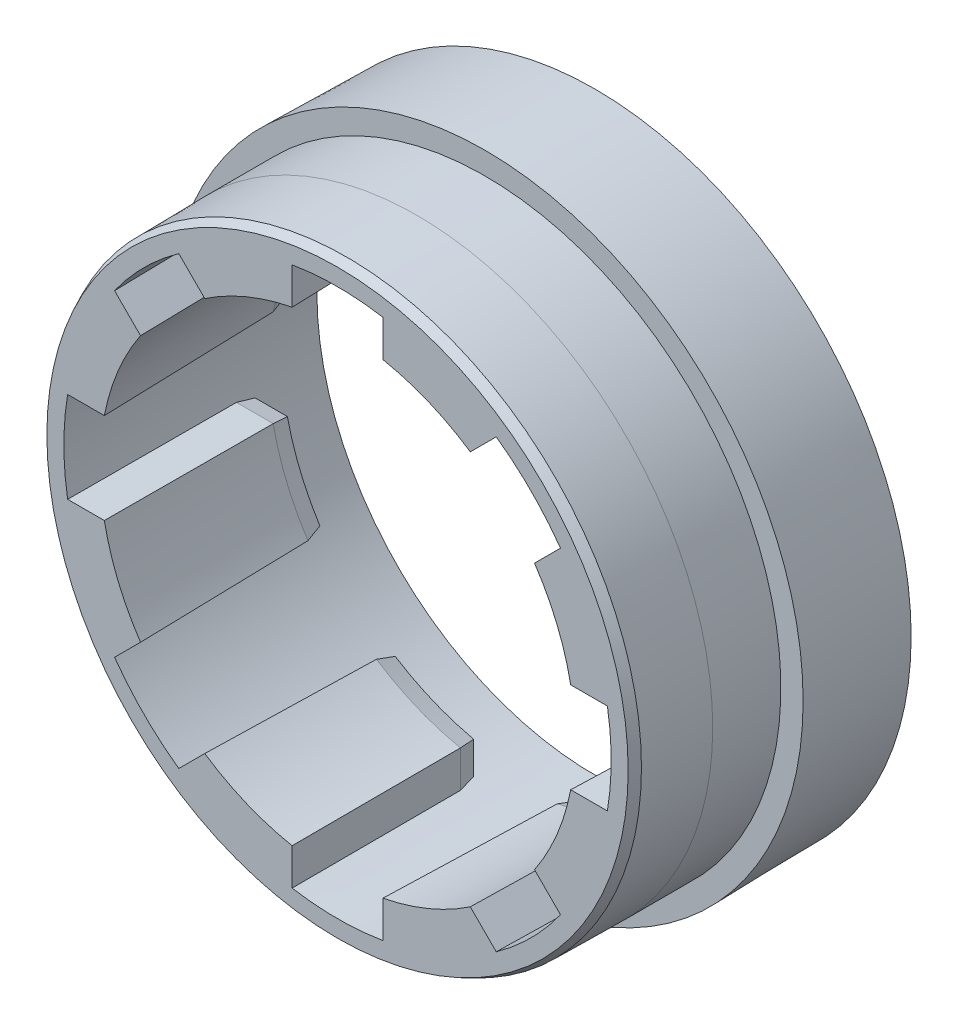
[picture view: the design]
ISO-10303-21;
HEADER;
FILE_DESCRIPTION(('STEP AP214'),'2;1');
FILE_NAME('part.step','',(''),(''),'','','');
FILE_SCHEMA(('AUTOMOTIVE_DESIGN { 1 0 10303 214 1 1 1 1 }'));
ENDSEC;
DATA;
#1=APPLICATION_CONTEXT('core data for automotive mechanical design processes');
#2=APPLICATION_PROTOCOL_DEFINITION('international standard','automotive_design',2000,#1);
#3=PRODUCT_CONTEXT('',#1,'mechanical');
#4=PRODUCT('Part','Part','',(#3));
#5=PRODUCT_RELATED_PRODUCT_CATEGORY('part','',(#4));
#6=PRODUCT_DEFINITION_FORMATION('','',#4);
#7=PRODUCT_DEFINITION_CONTEXT('part definition',#1,'design');
#8=PRODUCT_DEFINITION('design','',#6,#7);
#9=PRODUCT_DEFINITION_SHAPE('','',#8);
#10=(LENGTH_UNIT() NAMED_UNIT(*) SI_UNIT(.MILLI.,.METRE.));
#11=(NAMED_UNIT(*) PLANE_ANGLE_UNIT() SI_UNIT($,.RADIAN.));
#12=(NAMED_UNIT(*) SI_UNIT($,.STERADIAN.) SOLID_ANGLE_UNIT());
#13=UNCERTAINTY_MEASURE_WITH_UNIT(LENGTH_MEASURE(1.E-05),#10,'distance_accuracy_value','');
#14=(GEOMETRIC_REPRESENTATION_CONTEXT(3) GLOBAL_UNCERTAINTY_ASSIGNED_CONTEXT((#13)) GLOBAL_UNIT_ASSIGNED_CONTEXT((#10,
#11,#12)) REPRESENTATION_CONTEXT('',''));
#15=CARTESIAN_POINT('',(0.,0.,0.));
#16=DIRECTION('',(0.,0.,1.));
#17=DIRECTION('',(1.,0.,0.));
#18=AXIS2_PLACEMENT_3D('',#15,#16,#17);
#19=CARTESIAN_POINT('',(0.,0.,3.25));
#20=DIRECTION('',(0.,0.,-1.));
#21=DIRECTION('',(-1.,0.,0.));
#22=AXIS2_PLACEMENT_3D('',#19,#20,#21);
#23=CONICAL_SURFACE('',#22,5.23,0.0174532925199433);
#24=CARTESIAN_POINT('',(4.46424185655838,2.91006326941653,-2.42));
#25=CARTESIAN_POINT('',(4.44311687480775,2.91226582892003,-1.47499849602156));
#26=CARTESIAN_POINT('',(4.42195462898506,2.91443110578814,-0.529997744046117));
#27=CARTESIAN_POINT('',(4.37955560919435,2.91868709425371,1.36000225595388));
#28=CARTESIAN_POINT('',(4.35831883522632,2.92077780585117,2.30500150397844));
#29=CARTESIAN_POINT('',(4.33704479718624,2.92283123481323,3.25));
#30=B_SPLINE_CURVE_WITH_KNOTS('',3,(#24,#25,#26,#27,#28,#29),.UNSPECIFIED.,.F.,.F.,(4,2,4),(0.,
2.83572046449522,5.67144092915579),.UNSPECIFIED.);
#31=CARTESIAN_POINT('',(4.42173560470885,2.91443940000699,-0.520789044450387));
#32=VERTEX_POINT('',#31);
#33=CARTESIAN_POINT('',(4.33704479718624,2.92283123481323,3.25));
#34=VERTEX_POINT('',#33);
#35=EDGE_CURVE('E353',#32,#34,#30,.T.);
#36=ORIENTED_EDGE('',*,*,#35,.F.);
#37=CARTESIAN_POINT('',(0.,0.,-0.520789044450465));
#38=DIRECTION('',(0.,0.,1.));
#39=DIRECTION('',(1.,0.,0.));
#40=AXIS2_PLACEMENT_3D('',#37,#38,#39);
#41=CIRCLE('',#40,5.2958193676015);
#42=CARTESIAN_POINT('',(5.1874590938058,1.06581936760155,-0.52078904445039));
#43=VERTEX_POINT('',#42);
#44=EDGE_CURVE('E441',#32,#43,#41,.F.);
#45=ORIENTED_EDGE('',*,*,#44,.T.);
#46=CARTESIAN_POINT('',(5.13350757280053,1.00000000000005,3.25));
#47=CARTESIAN_POINT('',(5.15814058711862,1.0299003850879,1.53700808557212));
#48=CARTESIAN_POINT('',(5.18260361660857,1.05980081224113,-0.175986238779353));
#49=CARTESIAN_POINT('',(5.23118970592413,1.11960175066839,-3.60197970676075));
#50=CARTESIAN_POINT('',(5.25531276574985,1.14950226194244,-5.31497885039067));
#51=CARTESIAN_POINT('',(5.27926584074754,1.17940281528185,-7.02798040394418));
#52=B_SPLINE_CURVE_WITH_KNOTS('',3,(#46,#47,#48,#49,#50,#51),.UNSPECIFIED.,.F.,.F.,(4,2,4),(0.,
5.14028970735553,10.2805794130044),.UNSPECIFIED.);
#53=CARTESIAN_POINT('',(5.13350757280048,1.00000000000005,3.25));
#54=VERTEX_POINT('',#53);
#55=EDGE_CURVE('E767',#54,#43,#52,.T.);
#56=ORIENTED_EDGE('',*,*,#55,.F.);
#57=CARTESIAN_POINT('',(0.,0.,3.25));
#58=DIRECTION('',(0.,0.,-1.));
#59=DIRECTION('',(-1.,0.,0.));
#60=AXIS2_PLACEMENT_3D('',#57,#58,#59);
#61=CIRCLE('',#60,5.23);
#62=EDGE_CURVE('E428',#34,#54,#61,.T.);
#63=ORIENTED_EDGE('',*,*,#62,.F.);
#64=EDGE_LOOP('',(#36,#45,#56,#63));
#65=FACE_BOUND('',#64,.T.);
#66=ADVANCED_FACE('F17',(#65),#23,.F.);
#67=CARTESIAN_POINT('',(0.,0.,3.25));
#68=DIRECTION('',(0.,0.,-1.));
#69=DIRECTION('',(-1.,0.,0.));
#70=AXIS2_PLACEMENT_3D('',#67,#68,#69);
#71=CONICAL_SURFACE('',#70,5.23,0.0174532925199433);
#72=CARTESIAN_POINT('',(5.21442116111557,-1.09897021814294,-2.42));
#73=CARTESIAN_POINT('',(5.20104098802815,-1.08247515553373,-1.47499849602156));
#74=CARTESIAN_POINT('',(5.18760810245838,-1.06598010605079,-0.529997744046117));
#75=CARTESIAN_POINT('',(5.16063690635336,-1.03299003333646,1.36000225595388));
#76=CARTESIAN_POINT('',(5.14709859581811,-1.01649501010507,2.30500150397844));
#77=CARTESIAN_POINT('',(5.1335075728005,-0.999999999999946,3.25));
#78=B_SPLINE_CURVE_WITH_KNOTS('',3,(#72,#73,#74,#75,#76,#77),.UNSPECIFIED.,.F.,.F.,(4,2,4),(0.,
2.83572046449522,5.67144092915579),.UNSPECIFIED.);
#79=CARTESIAN_POINT('',(5.18745909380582,-1.06581936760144,-0.520789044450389));
#80=VERTEX_POINT('',#79);
#81=CARTESIAN_POINT('',(5.1335075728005,-0.999999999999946,3.25));
#82=VERTEX_POINT('',#81);
#83=EDGE_CURVE('E364',#80,#82,#78,.T.);
#84=ORIENTED_EDGE('',*,*,#83,.F.);
#85=CARTESIAN_POINT('',(0.,0.,-0.520789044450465));
#86=DIRECTION('',(0.,0.,1.));
#87=DIRECTION('',(1.,0.,0.));
#88=AXIS2_PLACEMENT_3D('',#85,#86,#87);
#89=CIRCLE('',#88,5.2958193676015);
#90=CARTESIAN_POINT('',(4.42173560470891,-2.9144394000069,-0.520789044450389));
#91=VERTEX_POINT('',#90);
#92=EDGE_CURVE('E1719',#80,#91,#89,.F.);
#93=ORIENTED_EDGE('',*,*,#92,.T.);
#94=CARTESIAN_POINT('',(4.33704479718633,-2.92283123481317,3.25));
#95=CARTESIAN_POINT('',(4.37560573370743,-2.91910664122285,1.53700808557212));
#96=CARTESIAN_POINT('',(4.41404650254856,-2.91526182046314,-0.175986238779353));
#97=CARTESIAN_POINT('',(4.49068770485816,-2.90733172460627,-3.60197970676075));
#98=CARTESIAN_POINT('',(4.52888813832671,-2.90324644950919,-5.31497885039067));
#99=CARTESIAN_POINT('',(4.56696840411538,-2.89904094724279,-7.02798040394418));
#100=B_SPLINE_CURVE_WITH_KNOTS('',3,(#94,#95,#96,#97,#98,#99),.UNSPECIFIED.,.F.,.F.,(4,2,4),(0.,
5.14028970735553,10.2805794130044),.UNSPECIFIED.);
#101=CARTESIAN_POINT('',(4.3370447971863,-2.92283123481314,3.25));
#102=VERTEX_POINT('',#101);
#103=EDGE_CURVE('E808',#102,#91,#100,.T.);
#104=ORIENTED_EDGE('',*,*,#103,.F.);
#105=EDGE_CURVE('E1029',#82,#102,#61,.T.);
#106=ORIENTED_EDGE('',*,*,#105,.F.);
#107=EDGE_LOOP('',(#84,#93,#104,#106));
#108=FACE_BOUND('',#107,.T.);
#109=ADVANCED_FACE('F741',(#108),#71,.F.);
#110=CARTESIAN_POINT('',(0.,0.,3.25));
#111=DIRECTION('',(0.,0.,-1.));
#112=DIRECTION('',(-1.,0.,0.));
#113=AXIS2_PLACEMENT_3D('',#110,#111,#112);
#114=CONICAL_SURFACE('',#113,5.23,0.0174532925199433);
#115=CARTESIAN_POINT('',(2.91006326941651,-4.46424185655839,-2.42));
#116=CARTESIAN_POINT('',(2.91226582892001,-4.44311687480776,-1.47499849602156));
#117=CARTESIAN_POINT('',(2.91443110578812,-4.42195462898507,-0.529997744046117));
#118=CARTESIAN_POINT('',(2.91868709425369,-4.37955560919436,1.36000225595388));
#119=CARTESIAN_POINT('',(2.92077780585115,-4.35831883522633,2.30500150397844));
#120=CARTESIAN_POINT('',(2.92283123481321,-4.33704479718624,3.25));
#121=B_SPLINE_CURVE_WITH_KNOTS('',3,(#115,#116,#117,#118,#119,#120),.UNSPECIFIED.,.F.,.F.,(4,2,
4),(0.,2.83572046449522,5.67144092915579),.UNSPECIFIED.);
#122=CARTESIAN_POINT('',(2.91443940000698,-4.42173560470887,-0.520789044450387));
#123=VERTEX_POINT('',#122);
#124=CARTESIAN_POINT('',(2.92283123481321,-4.33704479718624,3.25));
#125=VERTEX_POINT('',#124);
#126=EDGE_CURVE('E375',#123,#125,#121,.T.);
#127=ORIENTED_EDGE('',*,*,#126,.F.);
#128=CARTESIAN_POINT('',(0.,0.,-0.520789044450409));
#129=DIRECTION('',(0.,0.,1.));
#130=DIRECTION('',(1.,0.,0.));
#131=AXIS2_PLACEMENT_3D('',#128,#129,#130);
#132=CIRCLE('',#131,5.29581936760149);
#133=CARTESIAN_POINT('',(1.06581936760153,-5.18745909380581,-0.52078904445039));
#134=VERTEX_POINT('',#133);
#135=EDGE_CURVE('E1057',#123,#134,#132,.F.);
#136=ORIENTED_EDGE('',*,*,#135,.T.);
#137=CARTESIAN_POINT('',(1.00000000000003,-5.13350757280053,3.25));
#138=CARTESIAN_POINT('',(1.02990038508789,-5.15814058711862,1.53700808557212));
#139=CARTESIAN_POINT('',(1.05980081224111,-5.18260361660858,-0.175986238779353));
#140=CARTESIAN_POINT('',(1.11960175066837,-5.23118970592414,-3.60197970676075));
#141=CARTESIAN_POINT('',(1.14950226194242,-5.25531276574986,-5.31497885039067));
#142=CARTESIAN_POINT('',(1.17940281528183,-5.27926584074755,-7.02798040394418));
#143=B_SPLINE_CURVE_WITH_KNOTS('',3,(#137,#138,#139,#140,#141,#142),.UNSPECIFIED.,.F.,.F.,(4,2,
4),(0.,5.14028970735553,10.2805794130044),.UNSPECIFIED.);
#144=CARTESIAN_POINT('',(1.00000000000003,-5.13350757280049,3.25));
#145=VERTEX_POINT('',#144);
#146=EDGE_CURVE('E453',#145,#134,#143,.T.);
#147=ORIENTED_EDGE('',*,*,#146,.F.);
#148=EDGE_CURVE('E1030',#125,#145,#61,.T.);
#149=ORIENTED_EDGE('',*,*,#148,.F.);
#150=EDGE_LOOP('',(#127,#136,#147,#149));
#151=FACE_BOUND('',#150,.T.);
#152=ADVANCED_FACE('F748',(#151),#114,.F.);
#153=CARTESIAN_POINT('',(0.,0.,3.25));
#154=DIRECTION('',(0.,0.,-1.));
#155=DIRECTION('',(-1.,0.,0.));
#156=AXIS2_PLACEMENT_3D('',#153,#154,#155);
#157=CONICAL_SURFACE('',#156,5.23,0.0174532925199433);
#158=CARTESIAN_POINT('',(-1.09897021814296,-5.21442116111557,-2.42));
#159=CARTESIAN_POINT('',(-1.08247515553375,-5.20104098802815,-1.47499849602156));
#160=CARTESIAN_POINT('',(-1.0659801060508,-5.18760810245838,-0.529997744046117));
#161=CARTESIAN_POINT('',(-1.03299003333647,-5.16063690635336,1.36000225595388));
#162=CARTESIAN_POINT('',(-1.01649501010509,-5.1470985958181,2.30500150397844));
#163=CARTESIAN_POINT('',(-0.999999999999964,-5.1335075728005,3.25));
#164=B_SPLINE_CURVE_WITH_KNOTS('',3,(#158,#159,#160,#161,#162,#163),.UNSPECIFIED.,.F.,.F.,(4,2,
4),(0.,2.83572046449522,5.67144092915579),.UNSPECIFIED.);
#165=CARTESIAN_POINT('',(-1.06581936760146,-5.18745909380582,-0.520789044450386));
#166=VERTEX_POINT('',#165);
#167=CARTESIAN_POINT('',(-0.999999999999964,-5.1335075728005,3.25));
#168=VERTEX_POINT('',#167);
#169=EDGE_CURVE('E386',#166,#168,#164,.T.);
#170=ORIENTED_EDGE('',*,*,#169,.F.);
#171=CARTESIAN_POINT('',(0.,0.,-0.520789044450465));
#172=DIRECTION('',(0.,0.,1.));
#173=DIRECTION('',(1.,0.,0.));
#174=AXIS2_PLACEMENT_3D('',#171,#172,#173);
#175=CIRCLE('',#174,5.2958193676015);
#176=CARTESIAN_POINT('',(-2.91443940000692,-4.4217356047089,-0.520789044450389));
#177=VERTEX_POINT('',#176);
#178=EDGE_CURVE('E1048',#166,#177,#175,.F.);
#179=ORIENTED_EDGE('',*,*,#178,.T.);
#180=CARTESIAN_POINT('',(-2.92283123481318,-4.33704479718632,3.25));
#181=CARTESIAN_POINT('',(-2.91910664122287,-4.37560573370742,1.53700808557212));
#182=CARTESIAN_POINT('',(-2.91526182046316,-4.41404650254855,-0.175986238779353));
#183=CARTESIAN_POINT('',(-2.90733172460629,-4.49068770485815,-3.60197970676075));
#184=CARTESIAN_POINT('',(-2.9032464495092,-4.5288881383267,-5.31497885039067));
#185=CARTESIAN_POINT('',(-2.89904094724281,-4.56696840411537,-7.02798040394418));
#186=B_SPLINE_CURVE_WITH_KNOTS('',3,(#180,#181,#182,#183,#184,#185),.UNSPECIFIED.,.F.,.F.,(4,2,
4),(0.,5.14028970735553,10.2805794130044),.UNSPECIFIED.);
#187=CARTESIAN_POINT('',(-2.92283123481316,-4.33704479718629,3.25));
#188=VERTEX_POINT('',#187);
#189=EDGE_CURVE('E840',#188,#177,#186,.T.);
#190=ORIENTED_EDGE('',*,*,#189,.F.);
#191=EDGE_CURVE('E982',#168,#188,#61,.T.);
#192=ORIENTED_EDGE('',*,*,#191,.F.);
#193=EDGE_LOOP('',(#170,#179,#190,#192));
#194=FACE_BOUND('',#193,.T.);
#195=ADVANCED_FACE('F831',(#194),#157,.F.);
#196=CARTESIAN_POINT('',(0.,0.,3.25));
#197=DIRECTION('',(0.,0.,-1.));
#198=DIRECTION('',(-1.,0.,0.));
#199=AXIS2_PLACEMENT_3D('',#196,#197,#198);
#200=CONICAL_SURFACE('',#199,5.23,0.0174532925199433);
#201=CARTESIAN_POINT('',(-4.4642418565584,-2.91006326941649,-2.42));
#202=CARTESIAN_POINT('',(-4.44311687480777,-2.91226582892,-1.47499849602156));
#203=CARTESIAN_POINT('',(-4.42195462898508,-2.91443110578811,-0.529997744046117));
#204=CARTESIAN_POINT('',(-4.37955560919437,-2.91868709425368,1.36000225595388));
#205=CARTESIAN_POINT('',(-4.35831883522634,-2.92077780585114,2.30500150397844));
#206=CARTESIAN_POINT('',(-4.33704479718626,-2.9228312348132,3.25));
#207=B_SPLINE_CURVE_WITH_KNOTS('',3,(#201,#202,#203,#204,#205,#206),.UNSPECIFIED.,.F.,.F.,(4,2,
4),(0.,2.83572046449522,5.67144092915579),.UNSPECIFIED.);
#208=CARTESIAN_POINT('',(-4.42173560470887,-2.91443940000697,-0.520789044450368));
#209=VERTEX_POINT('',#208);
#210=CARTESIAN_POINT('',(-4.33704479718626,-2.9228312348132,3.25));
#211=VERTEX_POINT('',#210);
#212=EDGE_CURVE('E397',#209,#211,#207,.T.);
#213=ORIENTED_EDGE('',*,*,#212,.F.);
#214=CARTESIAN_POINT('',(0.,0.,-0.520789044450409));
#215=DIRECTION('',(0.,0.,1.));
#216=DIRECTION('',(1.,0.,0.));
#217=AXIS2_PLACEMENT_3D('',#214,#215,#216);
#218=CIRCLE('',#217,5.29581936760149);
#219=CARTESIAN_POINT('',(-5.18745909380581,-1.06581936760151,-0.520789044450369));
#220=VERTEX_POINT('',#219);
#221=EDGE_CURVE('E1054',#209,#220,#218,.F.);
#222=ORIENTED_EDGE('',*,*,#221,.T.);
#223=CARTESIAN_POINT('',(-5.13350757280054,-1.00000000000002,3.25));
#224=CARTESIAN_POINT('',(-5.15814058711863,-1.02990038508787,1.53700808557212));
#225=CARTESIAN_POINT('',(-5.18260361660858,-1.05980081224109,-0.175986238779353));
#226=CARTESIAN_POINT('',(-5.23118970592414,-1.11960175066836,-3.60197970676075));
#227=CARTESIAN_POINT('',(-5.25531276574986,-1.1495022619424,-5.31497885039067));
#228=CARTESIAN_POINT('',(-5.27926584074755,-1.17940281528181,-7.02798040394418));
#229=B_SPLINE_CURVE_WITH_KNOTS('',3,(#223,#224,#225,#226,#227,#228),.UNSPECIFIED.,.F.,.F.,(4,2,
4),(0.,5.14028970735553,10.2805794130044),.UNSPECIFIED.);
#230=CARTESIAN_POINT('',(-5.13350757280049,-1.00000000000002,3.25));
#231=VERTEX_POINT('',#230);
#232=EDGE_CURVE('E878',#231,#220,#229,.T.);
#233=ORIENTED_EDGE('',*,*,#232,.F.);
#234=EDGE_CURVE('E981',#211,#231,#61,.T.);
#235=ORIENTED_EDGE('',*,*,#234,.F.);
#236=EDGE_LOOP('',(#213,#222,#233,#235));
#237=FACE_BOUND('',#236,.T.);
#238=ADVANCED_FACE('F836',(#237),#200,.F.);
#239=CARTESIAN_POINT('',(0.,0.,3.25));
#240=DIRECTION('',(0.,0.,-1.));
#241=DIRECTION('',(-1.,0.,0.));
#242=AXIS2_PLACEMENT_3D('',#239,#240,#241);
#243=CONICAL_SURFACE('',#242,5.23,0.0174532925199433);
#244=CARTESIAN_POINT('',(-5.21442116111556,1.09897021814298,-2.42));
#245=CARTESIAN_POINT('',(-5.20104098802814,1.08247515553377,-1.47499849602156));
#246=CARTESIAN_POINT('',(-5.18760810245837,1.06598010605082,-0.529997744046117));
#247=CARTESIAN_POINT('',(-5.16063690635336,1.03299003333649,1.36000225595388));
#248=CARTESIAN_POINT('',(-5.1470985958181,1.01649501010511,2.30500150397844));
#249=CARTESIAN_POINT('',(-5.1335075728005,0.999999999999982,3.25));
#250=B_SPLINE_CURVE_WITH_KNOTS('',3,(#244,#245,#246,#247,#248,#249),.UNSPECIFIED.,.F.,.F.,(4,2,
4),(0.,2.83572046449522,5.67144092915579),.UNSPECIFIED.);
#251=CARTESIAN_POINT('',(-5.18745909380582,1.06581936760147,-0.52078904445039));
#252=VERTEX_POINT('',#251);
#253=CARTESIAN_POINT('',(-5.1335075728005,0.999999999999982,3.25));
#254=VERTEX_POINT('',#253);
#255=EDGE_CURVE('E408',#252,#254,#250,.T.);
#256=ORIENTED_EDGE('',*,*,#255,.F.);
#257=CARTESIAN_POINT('',(0.,0.,-0.520789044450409));
#258=DIRECTION('',(0.,0.,1.));
#259=DIRECTION('',(1.,0.,0.));
#260=AXIS2_PLACEMENT_3D('',#257,#258,#259);
#261=CIRCLE('',#260,5.29581936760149);
#262=CARTESIAN_POINT('',(-4.42173560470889,2.91443940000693,-0.520789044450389));
#263=VERTEX_POINT('',#262);
#264=EDGE_CURVE('E1066',#252,#263,#261,.F.);
#265=ORIENTED_EDGE('',*,*,#264,.T.);
#266=CARTESIAN_POINT('',(-4.33704479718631,2.9228312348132,3.25));
#267=CARTESIAN_POINT('',(-4.37560573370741,2.91910664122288,1.53700808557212));
#268=CARTESIAN_POINT('',(-4.41404650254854,2.91526182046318,-0.175986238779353));
#269=CARTESIAN_POINT('',(-4.49068770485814,2.9073317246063,-3.60197970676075));
#270=CARTESIAN_POINT('',(-4.52888813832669,2.90324644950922,-5.31497885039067));
#271=CARTESIAN_POINT('',(-4.56696840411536,2.89904094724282,-7.02798040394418));
#272=B_SPLINE_CURVE_WITH_KNOTS('',3,(#266,#267,#268,#269,#270,#271),.UNSPECIFIED.,.F.,.F.,(4,2,
4),(0.,5.14028970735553,10.2805794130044),.UNSPECIFIED.);
#273=CARTESIAN_POINT('',(-4.33704479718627,2.92283123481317,3.25));
#274=VERTEX_POINT('',#273);
#275=EDGE_CURVE('E918',#274,#263,#272,.T.);
#276=ORIENTED_EDGE('',*,*,#275,.F.);
#277=EDGE_CURVE('E977',#254,#274,#61,.T.);
#278=ORIENTED_EDGE('',*,*,#277,.F.);
#279=EDGE_LOOP('',(#256,#265,#276,#278));
#280=FACE_BOUND('',#279,.T.);
#281=ADVANCED_FACE('F954',(#280),#243,.F.);
#282=CARTESIAN_POINT('',(0.,0.,3.25));
#283=DIRECTION('',(0.,0.,-1.));
#284=DIRECTION('',(-1.,0.,0.));
#285=AXIS2_PLACEMENT_3D('',#282,#283,#284);
#286=CONICAL_SURFACE('',#285,5.23,0.0174532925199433);
#287=CARTESIAN_POINT('',(-2.91006326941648,4.46424185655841,-2.42));
#288=CARTESIAN_POINT('',(-2.91226582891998,4.44311687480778,-1.47499849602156));
#289=CARTESIAN_POINT('',(-2.91443110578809,4.42195462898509,-0.529997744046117));
#290=CARTESIAN_POINT('',(-2.91868709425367,4.37955560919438,1.36000225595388));
#291=CARTESIAN_POINT('',(-2.92077780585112,4.35831883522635,2.30500150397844));
#292=CARTESIAN_POINT('',(-2.92283123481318,4.33704479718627,3.25));
#293=B_SPLINE_CURVE_WITH_KNOTS('',3,(#287,#288,#289,#290,#291,#292),.UNSPECIFIED.,.F.,.F.,(4,2,
4),(0.,2.83572046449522,5.67144092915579),.UNSPECIFIED.);
#294=CARTESIAN_POINT('',(-2.91443940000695,4.42173560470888,-0.520789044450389));
#295=VERTEX_POINT('',#294);
#296=CARTESIAN_POINT('',(-2.92283123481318,4.33704479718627,3.25));
#297=VERTEX_POINT('',#296);
#298=EDGE_CURVE('E419',#295,#297,#293,.T.);
#299=ORIENTED_EDGE('',*,*,#298,.F.);
#300=CARTESIAN_POINT('',(0.,0.,-0.520789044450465));
#301=DIRECTION('',(0.,0.,1.));
#302=DIRECTION('',(1.,0.,0.));
#303=AXIS2_PLACEMENT_3D('',#300,#301,#302);
#304=CIRCLE('',#303,5.2958193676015);
#305=CARTESIAN_POINT('',(-1.06581936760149,5.18745909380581,-0.52078904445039));
#306=VERTEX_POINT('',#305);
#307=EDGE_CURVE('E1071',#295,#306,#304,.F.);
#308=ORIENTED_EDGE('',*,*,#307,.T.);
#309=CARTESIAN_POINT('',(-1.,5.13350757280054,3.25));
#310=CARTESIAN_POINT('',(-1.02990038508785,5.15814058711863,1.53700808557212));
#311=CARTESIAN_POINT('',(-1.05980081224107,5.18260361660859,-0.175986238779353));
#312=CARTESIAN_POINT('',(-1.11960175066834,5.23118970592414,-3.60197970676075));
#313=CARTESIAN_POINT('',(-1.14950226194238,5.25531276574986,-5.31497885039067));
#314=CARTESIAN_POINT('',(-1.17940281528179,5.27926584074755,-7.02798040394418));
#315=B_SPLINE_CURVE_WITH_KNOTS('',3,(#309,#310,#311,#312,#313,#314),.UNSPECIFIED.,.F.,.F.,(4,2,
4),(0.,5.14028970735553,10.2805794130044),.UNSPECIFIED.);
#316=CARTESIAN_POINT('',(-1.,5.13350757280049,3.25));
#317=VERTEX_POINT('',#316);
#318=EDGE_CURVE('E945',#317,#306,#315,.T.);
#319=ORIENTED_EDGE('',*,*,#318,.F.);
#320=EDGE_CURVE('E429',#297,#317,#61,.T.);
#321=ORIENTED_EDGE('',*,*,#320,.F.);
#322=EDGE_LOOP('',(#299,#308,#319,#321));
#323=FACE_BOUND('',#322,.T.);
#324=ADVANCED_FACE('F951',(#323),#286,.F.);
#325=CARTESIAN_POINT('',(0.,0.,3.25));
#326=DIRECTION('',(0.,0.,-1.));
#327=DIRECTION('',(-1.,0.,0.));
#328=AXIS2_PLACEMENT_3D('',#325,#326,#327);
#329=CONICAL_SURFACE('',#328,5.23,0.0174532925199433);
#330=CARTESIAN_POINT('',(1.09897021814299,5.21442116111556,-2.42));
#331=CARTESIAN_POINT('',(1.08247515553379,5.20104098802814,-1.47499849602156));
#332=CARTESIAN_POINT('',(1.06598010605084,5.18760810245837,-0.529997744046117));
#333=CARTESIAN_POINT('',(1.03299003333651,5.16063690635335,1.36000225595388));
#334=CARTESIAN_POINT('',(1.01649501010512,5.1470985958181,2.30500150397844));
#335=CARTESIAN_POINT('',(1.,5.13350757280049,3.25));
#336=B_SPLINE_CURVE_WITH_KNOTS('',3,(#330,#331,#332,#333,#334,#335),.UNSPECIFIED.,.F.,.F.,(4,2,
4),(0.,2.83572046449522,5.67144092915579),.UNSPECIFIED.);
#337=CARTESIAN_POINT('',(1.06581936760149,5.18745909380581,-0.520789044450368));
#338=VERTEX_POINT('',#337);
#339=CARTESIAN_POINT('',(1.,5.13350757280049,3.25));
#340=VERTEX_POINT('',#339);
#341=EDGE_CURVE('E983',#338,#340,#336,.T.);
#342=ORIENTED_EDGE('',*,*,#341,.F.);
#343=CARTESIAN_POINT('',(0.,0.,-0.520789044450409));
#344=DIRECTION('',(0.,0.,1.));
#345=DIRECTION('',(1.,0.,0.));
#346=AXIS2_PLACEMENT_3D('',#343,#344,#345);
#347=CIRCLE('',#346,5.29581936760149);
#348=CARTESIAN_POINT('',(2.91443940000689,4.42173560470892,-0.520789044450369));
#349=VERTEX_POINT('',#348);
#350=EDGE_CURVE('E1077',#338,#349,#347,.F.);
#351=ORIENTED_EDGE('',*,*,#350,.T.);
#352=CARTESIAN_POINT('',(2.92283123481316,4.33704479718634,3.25));
#353=CARTESIAN_POINT('',(2.91910664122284,4.37560573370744,1.53700808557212));
#354=CARTESIAN_POINT('',(2.91526182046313,4.41404650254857,-0.175986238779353));
#355=CARTESIAN_POINT('',(2.90733172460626,4.49068770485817,-3.60197970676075));
#356=CARTESIAN_POINT('',(2.90324644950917,4.52888813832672,-5.31497885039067));
#357=CARTESIAN_POINT('',(2.89904094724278,4.56696840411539,-7.02798040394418));
#358=B_SPLINE_CURVE_WITH_KNOTS('',3,(#352,#353,#354,#355,#356,#357),.UNSPECIFIED.,.F.,.F.,(4,2,
4),(0.,5.14028970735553,10.2805794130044),.UNSPECIFIED.);
#359=CARTESIAN_POINT('',(2.92283123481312,4.33704479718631,3.25));
#360=VERTEX_POINT('',#359);
#361=EDGE_CURVE('E1002',#360,#349,#358,.T.);
#362=ORIENTED_EDGE('',*,*,#361,.F.);
#363=EDGE_CURVE('E344',#340,#360,#61,.T.);
#364=ORIENTED_EDGE('',*,*,#363,.F.);
#365=EDGE_LOOP('',(#342,#351,#362,#364));
#366=FACE_BOUND('',#365,.T.);
#367=ADVANCED_FACE('F754',(#366),#329,.F.);
#368=CARTESIAN_POINT('',(1.,5.,3.25));
#369=DIRECTION('',(-0.999847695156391,0.,-0.0174524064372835));
#370=DIRECTION('',(-0.0174524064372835,0.,0.999847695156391));
#371=AXIS2_PLACEMENT_3D('',#368,#369,#370);
#372=PLANE('',#371);
#373=CARTESIAN_POINT('',(1.09897021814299,6.02455605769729,-2.42));
#374=CARTESIAN_POINT('',(1.08247515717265,6.01079841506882,-1.47499858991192));
#375=CARTESIAN_POINT('',(1.06598010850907,5.99699266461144,-0.529997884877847));
#376=CARTESIAN_POINT('',(1.03299003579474,5.96928494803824,1.36000211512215));
#377=CARTESIAN_POINT('',(1.01649501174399,5.95538298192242,2.30500141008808));
#378=CARTESIAN_POINT('',(1.,5.94143290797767,3.25));
#379=B_SPLINE_CURVE_WITH_KNOTS('',3,(#373,#374,#375,#376,#377,#378),.UNSPECIFIED.,.F.,.F.,(4,2,
4),(0.,2.83573644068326,5.67147288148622),.UNSPECIFIED.);
#380=CARTESIAN_POINT('',(1.06581936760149,5.99684163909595,-0.520789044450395));
#381=VERTEX_POINT('',#380);
#382=CARTESIAN_POINT('',(1.,5.94143290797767,3.25));
#383=VERTEX_POINT('',#382);
#384=EDGE_CURVE('E991',#381,#383,#379,.T.);
#385=ORIENTED_EDGE('',*,*,#384,.F.);
#386=DIRECTION('',(0.,1.,0.));
#387=VECTOR('',#386,1.);
#388=CARTESIAN_POINT('',(1.06581936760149,5.29520923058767,-0.520789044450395));
#389=LINE('',#388,#387);
#390=EDGE_CURVE('E1159',#381,#338,#389,.F.);
#391=ORIENTED_EDGE('',*,*,#390,.T.);
#392=ORIENTED_EDGE('',*,*,#341,.T.);
#393=DIRECTION('',(0.,1.,0.));
#394=VECTOR('',#393,1.);
#395=CARTESIAN_POINT('',(1.,5.,3.25));
#396=LINE('',#395,#394);
#397=EDGE_CURVE('E422',#340,#383,#396,.T.);
#398=ORIENTED_EDGE('',*,*,#397,.T.);
#399=EDGE_LOOP('',(#385,#391,#392,#398));
#400=FACE_BOUND('',#399,.T.);
#401=ADVANCED_FACE('F1007',(#400),#372,.T.);
#402=CARTESIAN_POINT('',(-1.,5.,3.25));
#403=DIRECTION('',(0.999847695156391,0.,-0.0174524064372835));
#404=DIRECTION('',(-0.0174524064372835,0.,-0.999847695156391));
#405=AXIS2_PLACEMENT_3D('',#402,#403,#404);
#406=PLANE('',#405);
#407=ORIENTED_EDGE('',*,*,#318,.T.);
#408=DIRECTION('',(0.,-1.,0.));
#409=VECTOR('',#408,1.);
#410=CARTESIAN_POINT('',(-1.06581936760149,6.00267778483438,-0.520789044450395));
#411=LINE('',#410,#409);
#412=CARTESIAN_POINT('',(-1.06581936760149,5.99684163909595,-0.520789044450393));
#413=VERTEX_POINT('',#412);
#414=EDGE_CURVE('E1146',#306,#413,#411,.F.);
#415=ORIENTED_EDGE('',*,*,#414,.T.);
#416=CARTESIAN_POINT('',(-1.56885999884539,6.40450372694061,-29.3399675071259));
#417=CARTESIAN_POINT('',(-1.52145465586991,6.36730875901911,-26.6241172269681));
#418=CARTESIAN_POINT('',(-1.47404938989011,6.32979091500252,-23.9082713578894));
#419=CARTESIAN_POINT('',(-1.37923902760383,6.25407165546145,-18.4765893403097));
#420=CARTESIAN_POINT('',(-1.33183393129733,6.21587023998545,-15.760753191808));
#421=CARTESIAN_POINT('',(-1.23702391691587,6.13874601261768,-10.3290911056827));
#422=CARTESIAN_POINT('',(-1.18961899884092,6.09982320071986,-7.61326516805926));
#423=CARTESIAN_POINT('',(-1.09480935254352,6.02121264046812,-2.18162416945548));
#424=CARTESIAN_POINT('',(-1.04740462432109,5.98152489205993,0.534190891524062));
#425=CARTESIAN_POINT('',(-1.,5.94143290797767,3.25));
#426=B_SPLINE_CURVE_WITH_KNOTS('',3,(#416,#417,#418,#419,#420,#421,#422,#423,#424,#425),
.UNSPECIFIED.,.F.,.F.,(4,2,2,2,4),(0.,8.14955588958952,16.2991112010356,24.4486665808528,
32.5982225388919),.UNSPECIFIED.);
#427=CARTESIAN_POINT('',(-1.,5.94143290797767,3.25));
#428=VERTEX_POINT('',#427);
#429=EDGE_CURVE('E444',#413,#428,#426,.T.);
#430=ORIENTED_EDGE('',*,*,#429,.T.);
#431=DIRECTION('',(0.,-1.,0.));
#432=VECTOR('',#431,1.);
#433=CARTESIAN_POINT('',(-1.,5.,3.25));
#434=LINE('',#433,#432);
#435=EDGE_CURVE('E418',#428,#317,#434,.T.);
#436=ORIENTED_EDGE('',*,*,#435,.T.);
#437=EDGE_LOOP('',(#407,#415,#430,#436));
#438=FACE_BOUND('',#437,.T.);
#439=ADVANCED_FACE('F935',(#438),#406,.T.);
#440=CARTESIAN_POINT('',(-2.8284271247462,4.24264068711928,3.25));
#441=DIRECTION('',(-0.706999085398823,-0.706999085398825,-0.0174524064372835));
#442=DIRECTION('',(0.707106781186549,-0.707106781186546,0.));
#443=AXIS2_PLACEMENT_3D('',#440,#441,#442);
#444=PLANE('',#443);
#445=CARTESIAN_POINT('',(-3.48291514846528,5.03709373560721,-2.42));
#446=CARTESIAN_POINT('',(-3.48485079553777,5.01570184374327,-1.47499858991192));
#447=CARTESIAN_POINT('',(-3.48675241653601,4.99427594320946,-0.529997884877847));
#448=CARTESIAN_POINT('',(-3.49048760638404,4.95135612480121,1.36000211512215));
#449=CARTESIAN_POINT('',(-3.49232117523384,4.92986220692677,2.30500141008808));
#450=CARTESIAN_POINT('',(-3.49412071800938,4.90833428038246,3.25));
#451=B_SPLINE_CURVE_WITH_KNOTS('',3,(#445,#446,#447,#448,#449,#450),.UNSPECIFIED.,.F.,.F.,(4,2,
4),(0.,2.83573644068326,5.67147288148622),.UNSPECIFIED.);
#452=CARTESIAN_POINT('',(-3.48675928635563,4.99405549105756,-0.520789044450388));
#453=VERTEX_POINT('',#452);
#454=CARTESIAN_POINT('',(-3.49412071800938,4.90833428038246,3.25));
#455=VERTEX_POINT('',#454);
#456=EDGE_CURVE('E904',#453,#455,#451,.T.);
#457=ORIENTED_EDGE('',*,*,#456,.F.);
#458=DIRECTION('',(-0.707106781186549,0.707106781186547,0.));
#459=VECTOR('',#458,1.);
#460=CARTESIAN_POINT('',(-2.99063025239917,4.49792645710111,-0.520789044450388));
#461=LINE('',#460,#459);
#462=EDGE_CURVE('E681',#453,#295,#461,.F.);
#463=ORIENTED_EDGE('',*,*,#462,.T.);
#464=ORIENTED_EDGE('',*,*,#298,.T.);
#465=DIRECTION('',(-0.707106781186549,0.707106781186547,0.));
#466=VECTOR('',#465,1.);
#467=CARTESIAN_POINT('',(-2.8284271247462,4.24264068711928,3.25));
#468=LINE('',#467,#466);
#469=EDGE_CURVE('E411',#297,#455,#468,.T.);
#470=ORIENTED_EDGE('',*,*,#469,.T.);
#471=EDGE_LOOP('',(#457,#463,#464,#470));
#472=FACE_BOUND('',#471,.T.);
#473=ADVANCED_FACE('F928',(#472),#444,.T.);
#474=CARTESIAN_POINT('',(-4.24264068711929,2.82842712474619,3.25));
#475=DIRECTION('',(0.706999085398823,0.706999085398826,-0.0174524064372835));
#476=DIRECTION('',(-0.707106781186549,0.707106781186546,0.));
#477=AXIS2_PLACEMENT_3D('',#474,#475,#476);
#478=PLANE('',#477);
#479=ORIENTED_EDGE('',*,*,#275,.T.);
#480=DIRECTION('',(0.707106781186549,-0.707106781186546,0.));
#481=VECTOR('',#480,1.);
#482=CARTESIAN_POINT('',(-4.99818226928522,3.49088606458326,-0.520789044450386));
#483=LINE('',#482,#481);
#484=CARTESIAN_POINT('',(-4.99405549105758,3.48675928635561,-0.520789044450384));
#485=VERTEX_POINT('',#484);
#486=EDGE_CURVE('E667',#263,#485,#483,.F.);
#487=ORIENTED_EDGE('',*,*,#486,.T.);
#488=CARTESIAN_POINT('',(-5.63824588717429,3.41928915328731,-29.3502427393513));
#489=CARTESIAN_POINT('',(-5.57840615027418,3.42651183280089,-26.6335361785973));
#490=CARTESIAN_POINT('',(-5.51833803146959,3.4335060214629,-23.9168340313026));
#491=CARTESIAN_POINT('',(-5.39771827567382,3.44701064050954,-18.4834394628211));
#492=CARTESIAN_POINT('',(-5.33716663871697,3.4535210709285,-15.7667470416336));
#493=CARTESIAN_POINT('',(-5.21555308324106,3.46603139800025,-10.3333724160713));
#494=CARTESIAN_POINT('',(-5.15449116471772,3.47203129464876,-7.61669021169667));
#495=CARTESIAN_POINT('',(-5.03182623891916,3.48348973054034,-2.18333668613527));
#496=CARTESIAN_POINT('',(-4.97022323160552,3.48894826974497,0.533334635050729));
#497=CARTESIAN_POINT('',(-4.90833428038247,3.49412071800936,3.25));
#498=B_SPLINE_CURVE_WITH_KNOTS('',3,(#488,#489,#490,#491,#492,#493,#494,#495,#496,#497),
.UNSPECIFIED.,.F.,.F.,(4,2,2,2,4),(0.,8.15212532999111,16.3042500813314,24.4563749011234,
32.6085002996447),.UNSPECIFIED.);
#499=CARTESIAN_POINT('',(-4.90833428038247,3.49412071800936,3.25));
#500=VERTEX_POINT('',#499);
#501=EDGE_CURVE('E414',#485,#500,#498,.T.);
#502=ORIENTED_EDGE('',*,*,#501,.T.);
#503=DIRECTION('',(0.707106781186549,-0.707106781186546,0.));
#504=VECTOR('',#503,1.);
#505=CARTESIAN_POINT('',(-4.24264068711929,2.82842712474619,3.25));
#506=LINE('',#505,#504);
#507=EDGE_CURVE('E407',#500,#274,#506,.T.);
#508=ORIENTED_EDGE('',*,*,#507,.T.);
#509=EDGE_LOOP('',(#479,#487,#502,#508));
#510=FACE_BOUND('',#509,.T.);
#511=ADVANCED_FACE('F924',(#510),#478,.T.);
#512=CARTESIAN_POINT('',(-5.,0.999999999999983,3.25));
#513=DIRECTION('',(0.,-0.999847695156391,-0.0174524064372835));
#514=DIRECTION('',(0.,0.0174524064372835,-0.999847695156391));
#515=AXIS2_PLACEMENT_3D('',#512,#513,#514);
#516=PLANE('',#515);
#517=CARTESIAN_POINT('',(-6.02455605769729,1.09897021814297,-2.42));
#518=CARTESIAN_POINT('',(-6.01079841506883,1.08247515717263,-1.47499858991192));
#519=CARTESIAN_POINT('',(-5.99699266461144,1.06598010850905,-0.529997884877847));
#520=CARTESIAN_POINT('',(-5.96928494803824,1.03299003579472,1.36000211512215));
#521=CARTESIAN_POINT('',(-5.95538298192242,1.01649501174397,2.30500141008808));
#522=CARTESIAN_POINT('',(-5.94143290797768,0.99999999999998,3.25));
#523=B_SPLINE_CURVE_WITH_KNOTS('',3,(#517,#518,#519,#520,#521,#522),.UNSPECIFIED.,.F.,.F.,(4,2,
4),(0.,2.83573644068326,5.67147288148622),.UNSPECIFIED.);
#524=CARTESIAN_POINT('',(-5.99684163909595,1.06581936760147,-0.520789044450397));
#525=VERTEX_POINT('',#524);
#526=CARTESIAN_POINT('',(-5.94143290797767,0.99999999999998,3.25));
#527=VERTEX_POINT('',#526);
#528=EDGE_CURVE('E885',#525,#527,#523,.T.);
#529=ORIENTED_EDGE('',*,*,#528,.F.);
#530=DIRECTION('',(-1.,0.,0.));
#531=VECTOR('',#530,1.);
#532=CARTESIAN_POINT('',(-5.29520923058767,1.06581936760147,-0.520789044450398));
#533=LINE('',#532,#531);
#534=EDGE_CURVE('E972',#525,#252,#533,.F.);
#535=ORIENTED_EDGE('',*,*,#534,.T.);
#536=ORIENTED_EDGE('',*,*,#255,.T.);
#537=DIRECTION('',(-1.,0.,0.));
#538=VECTOR('',#537,1.);
#539=CARTESIAN_POINT('',(-5.,0.999999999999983,3.25));
#540=LINE('',#539,#538);
#541=EDGE_CURVE('E400',#254,#527,#540,.T.);
#542=ORIENTED_EDGE('',*,*,#541,.T.);
#543=EDGE_LOOP('',(#529,#535,#536,#542));
#544=FACE_BOUND('',#543,.T.);
#545=ADVANCED_FACE('F927',(#544),#516,.T.);
#546=CARTESIAN_POINT('',(-5.,-1.00000000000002,3.25));
#547=DIRECTION('',(0.,0.999847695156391,-0.0174524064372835));
#548=DIRECTION('',(0.,0.0174524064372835,0.999847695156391));
#549=AXIS2_PLACEMENT_3D('',#546,#547,#548);
#550=PLANE('',#549);
#551=ORIENTED_EDGE('',*,*,#232,.T.);
#552=DIRECTION('',(1.,0.,0.));
#553=VECTOR('',#552,1.);
#554=CARTESIAN_POINT('',(-6.00267778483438,-1.06581936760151,-0.520789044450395));
#555=LINE('',#554,#553);
#556=CARTESIAN_POINT('',(-5.99684163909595,-1.06581936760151,-0.520789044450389));
#557=VERTEX_POINT('',#556);
#558=EDGE_CURVE('E1268',#220,#557,#555,.F.);
#559=ORIENTED_EDGE('',*,*,#558,.T.);
#560=CARTESIAN_POINT('',(-6.4045037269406,-1.56885999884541,-29.3399675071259));
#561=CARTESIAN_POINT('',(-6.3673087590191,-1.52145465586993,-26.6241172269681));
#562=CARTESIAN_POINT('',(-6.32979091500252,-1.47404938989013,-23.9082713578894));
#563=CARTESIAN_POINT('',(-6.25407165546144,-1.37923902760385,-18.4765893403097));
#564=CARTESIAN_POINT('',(-6.21587023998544,-1.33183393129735,-15.760753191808));
#565=CARTESIAN_POINT('',(-6.13874601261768,-1.23702391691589,-10.3290911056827));
#566=CARTESIAN_POINT('',(-6.09982320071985,-1.18961899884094,-7.61326516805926));
#567=CARTESIAN_POINT('',(-6.02121264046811,-1.09480935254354,-2.18162416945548));
#568=CARTESIAN_POINT('',(-5.98152489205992,-1.04740462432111,0.534190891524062));
#569=CARTESIAN_POINT('',(-5.94143290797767,-1.00000000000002,3.25));
#570=B_SPLINE_CURVE_WITH_KNOTS('',3,(#560,#561,#562,#563,#564,#565,#566,#567,#568,#569),
.UNSPECIFIED.,.F.,.F.,(4,2,2,2,4),(0.,8.14955588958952,16.2991112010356,24.4486665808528,
32.5982225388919),.UNSPECIFIED.);
#571=CARTESIAN_POINT('',(-5.94143290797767,-1.00000000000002,3.25));
#572=VERTEX_POINT('',#571);
#573=EDGE_CURVE('E403',#557,#572,#570,.T.);
#574=ORIENTED_EDGE('',*,*,#573,.T.);
#575=DIRECTION('',(1.,0.,0.));
#576=VECTOR('',#575,1.);
#577=CARTESIAN_POINT('',(-5.,-1.00000000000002,3.25));
#578=LINE('',#577,#576);
#579=EDGE_CURVE('E396',#572,#231,#578,.T.);
#580=ORIENTED_EDGE('',*,*,#579,.T.);
#581=EDGE_LOOP('',(#551,#559,#574,#580));
#582=FACE_BOUND('',#581,.T.);
#583=ADVANCED_FACE('F863',(#582),#550,.T.);
#584=CARTESIAN_POINT('',(-4.24264068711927,-2.82842712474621,3.25));
#585=DIRECTION('',(0.706999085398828,-0.706999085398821,-0.0174524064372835));
#586=DIRECTION('',(0.707106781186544,0.707106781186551,0.));
#587=AXIS2_PLACEMENT_3D('',#584,#585,#586);
#588=PLANE('',#587);
#589=CARTESIAN_POINT('',(-5.0370937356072,-3.4829151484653,-2.42));
#590=CARTESIAN_POINT('',(-5.01570184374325,-3.48485079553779,-1.47499858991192));
#591=CARTESIAN_POINT('',(-4.99427594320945,-3.48675241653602,-0.529997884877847));
#592=CARTESIAN_POINT('',(-4.9513561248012,-3.49048760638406,1.36000211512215));
#593=CARTESIAN_POINT('',(-4.92986220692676,-3.49232117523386,2.30500141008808));
#594=CARTESIAN_POINT('',(-4.90833428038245,-3.4941207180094,3.25));
#595=B_SPLINE_CURVE_WITH_KNOTS('',3,(#589,#590,#591,#592,#593,#594),.UNSPECIFIED.,.F.,.F.,(4,2,
4),(0.,2.83573644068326,5.67147288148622),.UNSPECIFIED.);
#596=CARTESIAN_POINT('',(-4.99405549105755,-3.48675928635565,-0.52078904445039));
#597=VERTEX_POINT('',#596);
#598=CARTESIAN_POINT('',(-4.90833428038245,-3.4941207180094,3.25));
#599=VERTEX_POINT('',#598);
#600=EDGE_CURVE('E847',#597,#599,#595,.T.);
#601=ORIENTED_EDGE('',*,*,#600,.F.);
#602=DIRECTION('',(-0.707106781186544,-0.707106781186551,0.));
#603=VECTOR('',#602,1.);
#604=CARTESIAN_POINT('',(-4.4979264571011,-2.99063025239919,-0.520789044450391));
#605=LINE('',#604,#603);
#606=EDGE_CURVE('E642',#597,#209,#605,.F.);
#607=ORIENTED_EDGE('',*,*,#606,.T.);
#608=ORIENTED_EDGE('',*,*,#212,.T.);
#609=DIRECTION('',(-0.707106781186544,-0.707106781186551,0.));
#610=VECTOR('',#609,1.);
#611=CARTESIAN_POINT('',(-4.24264068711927,-2.82842712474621,3.25));
#612=LINE('',#611,#610);
#613=EDGE_CURVE('E389',#211,#599,#612,.T.);
#614=ORIENTED_EDGE('',*,*,#613,.T.);
#615=EDGE_LOOP('',(#601,#607,#608,#614));
#616=FACE_BOUND('',#615,.T.);
#617=ADVANCED_FACE('F857',(#616),#588,.T.);
#618=CARTESIAN_POINT('',(-2.82842712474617,-4.2426406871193,3.25));
#619=DIRECTION('',(-0.706999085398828,0.70699908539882,-0.0174524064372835));
#620=DIRECTION('',(-0.707106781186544,-0.707106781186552,0.));
#621=AXIS2_PLACEMENT_3D('',#618,#619,#620);
#622=PLANE('',#621);
#623=ORIENTED_EDGE('',*,*,#189,.T.);
#624=DIRECTION('',(0.707106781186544,0.707106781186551,0.));
#625=VECTOR('',#624,1.);
#626=CARTESIAN_POINT('',(-3.49088606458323,-4.99818226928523,-0.520789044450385));
#627=LINE('',#626,#625);
#628=CARTESIAN_POINT('',(-3.4867592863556,-4.99405549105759,-0.520789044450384));
#629=VERTEX_POINT('',#628);
#630=EDGE_CURVE('E604',#177,#629,#627,.F.);
#631=ORIENTED_EDGE('',*,*,#630,.T.);
#632=CARTESIAN_POINT('',(-3.41928915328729,-5.63824588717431,-29.3502427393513));
#633=CARTESIAN_POINT('',(-3.42651183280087,-5.5784061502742,-26.6335361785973));
#634=CARTESIAN_POINT('',(-3.43350602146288,-5.5183380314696,-23.9168340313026));
#635=CARTESIAN_POINT('',(-3.44701064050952,-5.39771827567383,-18.4834394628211));
#636=CARTESIAN_POINT('',(-3.45352107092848,-5.33716663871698,-15.7667470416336));
#637=CARTESIAN_POINT('',(-3.46603139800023,-5.21555308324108,-10.3333724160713));
#638=CARTESIAN_POINT('',(-3.47203129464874,-5.15449116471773,-7.61669021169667));
#639=CARTESIAN_POINT('',(-3.48348973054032,-5.03182623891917,-2.18333668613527));
#640=CARTESIAN_POINT('',(-3.48894826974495,-4.97022323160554,0.533334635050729));
#641=CARTESIAN_POINT('',(-3.49412071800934,-4.90833428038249,3.25));
#642=B_SPLINE_CURVE_WITH_KNOTS('',3,(#632,#633,#634,#635,#636,#637,#638,#639,#640,#641),
.UNSPECIFIED.,.F.,.F.,(4,2,2,2,4),(0.,8.15212532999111,16.3042500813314,24.4563749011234,
32.6085002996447),.UNSPECIFIED.);
#643=CARTESIAN_POINT('',(-3.49412071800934,-4.90833428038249,3.25));
#644=VERTEX_POINT('',#643);
#645=EDGE_CURVE('E392',#629,#644,#642,.T.);
#646=ORIENTED_EDGE('',*,*,#645,.T.);
#647=DIRECTION('',(0.707106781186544,0.707106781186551,0.));
#648=VECTOR('',#647,1.);
#649=CARTESIAN_POINT('',(-2.82842712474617,-4.2426406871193,3.25));
#650=LINE('',#649,#648);
#651=EDGE_CURVE('E385',#644,#188,#650,.T.);
#652=ORIENTED_EDGE('',*,*,#651,.T.);
#653=EDGE_LOOP('',(#623,#631,#646,#652));
#654=FACE_BOUND('',#653,.T.);
#655=ADVANCED_FACE('F853',(#654),#622,.T.);
#656=CARTESIAN_POINT('',(-0.999999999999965,-5.,3.25));
#657=DIRECTION('',(0.999847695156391,0.,-0.0174524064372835));
#658=DIRECTION('',(-0.0174524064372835,0.,-0.999847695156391));
#659=AXIS2_PLACEMENT_3D('',#656,#657,#658);
#660=PLANE('',#659);
#661=CARTESIAN_POINT('',(-1.09897021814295,-6.0245560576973,-2.42));
#662=CARTESIAN_POINT('',(-1.08247515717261,-6.01079841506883,-1.47499858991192));
#663=CARTESIAN_POINT('',(-1.06598010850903,-5.99699266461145,-0.529997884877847));
#664=CARTESIAN_POINT('',(-1.0329900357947,-5.96928494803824,1.36000211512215));
#665=CARTESIAN_POINT('',(-1.01649501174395,-5.95538298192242,2.30500141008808));
#666=CARTESIAN_POINT('',(-0.999999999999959,-5.94143290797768,3.25));
#667=B_SPLINE_CURVE_WITH_KNOTS('',3,(#661,#662,#663,#664,#665,#666),.UNSPECIFIED.,.F.,.F.,(4,2,
4),(0.,2.83573644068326,5.67147288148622),.UNSPECIFIED.);
#668=CARTESIAN_POINT('',(-1.06581936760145,-5.99684163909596,-0.520789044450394));
#669=VERTEX_POINT('',#668);
#670=CARTESIAN_POINT('',(-0.999999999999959,-5.94143290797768,3.25));
#671=VERTEX_POINT('',#670);
#672=EDGE_CURVE('E445',#669,#671,#667,.T.);
#673=ORIENTED_EDGE('',*,*,#672,.F.);
#674=DIRECTION('',(0.,-1.,0.));
#675=VECTOR('',#674,1.);
#676=CARTESIAN_POINT('',(-1.06581936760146,-5.29520923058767,-0.520789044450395));
#677=LINE('',#676,#675);
#678=EDGE_CURVE('E1693',#669,#166,#677,.F.);
#679=ORIENTED_EDGE('',*,*,#678,.T.);
#680=ORIENTED_EDGE('',*,*,#169,.T.);
#681=DIRECTION('',(0.,-1.,0.));
#682=VECTOR('',#681,1.);
#683=CARTESIAN_POINT('',(-0.999999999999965,-5.,3.25));
#684=LINE('',#683,#682);
#685=EDGE_CURVE('E378',#168,#671,#684,.T.);
#686=ORIENTED_EDGE('',*,*,#685,.T.);
#687=EDGE_LOOP('',(#673,#679,#680,#686));
#688=FACE_BOUND('',#687,.T.);
#689=ADVANCED_FACE('F460',(#688),#660,.T.);
#690=CARTESIAN_POINT('',(1.00000000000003,-5.,3.25));
#691=DIRECTION('',(-0.999847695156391,0.,-0.0174524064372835));
#692=DIRECTION('',(-0.0174524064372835,0.,0.999847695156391));
#693=AXIS2_PLACEMENT_3D('',#690,#691,#692);
#694=PLANE('',#693);
#695=ORIENTED_EDGE('',*,*,#146,.T.);
#696=DIRECTION('',(0.,1.,0.));
#697=VECTOR('',#696,1.);
#698=CARTESIAN_POINT('',(1.06581936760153,-6.00267778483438,-0.520789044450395));
#699=LINE('',#698,#697);
#700=CARTESIAN_POINT('',(1.06581936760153,-5.99684163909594,-0.520789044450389));
#701=VERTEX_POINT('',#700);
#702=EDGE_CURVE('E1687',#134,#701,#699,.F.);
#703=ORIENTED_EDGE('',*,*,#702,.T.);
#704=CARTESIAN_POINT('',(1.56885999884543,-6.4045037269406,-29.3399675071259));
#705=CARTESIAN_POINT('',(1.52145465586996,-6.3673087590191,-26.6241172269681));
#706=CARTESIAN_POINT('',(1.47404938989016,-6.32979091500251,-23.9082713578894));
#707=CARTESIAN_POINT('',(1.37923902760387,-6.25407165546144,-18.4765893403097));
#708=CARTESIAN_POINT('',(1.33183393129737,-6.21587023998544,-15.760753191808));
#709=CARTESIAN_POINT('',(1.23702391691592,-6.13874601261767,-10.3290911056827));
#710=CARTESIAN_POINT('',(1.18961899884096,-6.09982320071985,-7.61326516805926));
#711=CARTESIAN_POINT('',(1.09480935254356,-6.02121264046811,-2.18162416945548));
#712=CARTESIAN_POINT('',(1.04740462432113,-5.98152489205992,0.534190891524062));
#713=CARTESIAN_POINT('',(1.00000000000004,-5.94143290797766,3.25));
#714=B_SPLINE_CURVE_WITH_KNOTS('',3,(#704,#705,#706,#707,#708,#709,#710,#711,#712,#713),
.UNSPECIFIED.,.F.,.F.,(4,2,2,2,4),(0.,8.14955588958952,16.2991112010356,24.4486665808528,
32.5982225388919),.UNSPECIFIED.);
#715=CARTESIAN_POINT('',(1.00000000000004,-5.94143290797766,3.25));
#716=VERTEX_POINT('',#715);
#717=EDGE_CURVE('E381',#701,#716,#714,.T.);
#718=ORIENTED_EDGE('',*,*,#717,.T.);
#719=DIRECTION('',(0.,1.,0.));
#720=VECTOR('',#719,1.);
#721=CARTESIAN_POINT('',(1.00000000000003,-5.,3.25));
#722=LINE('',#721,#720);
#723=EDGE_CURVE('E374',#716,#145,#722,.T.);
#724=ORIENTED_EDGE('',*,*,#723,.T.);
#725=EDGE_LOOP('',(#695,#703,#718,#724));
#726=FACE_BOUND('',#725,.T.);
#727=ADVANCED_FACE('F487',(#726),#694,.T.);
#728=CARTESIAN_POINT('',(2.82842712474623,-4.24264068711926,3.25));
#729=DIRECTION('',(0.706999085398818,0.70699908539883,-0.0174524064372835));
#730=DIRECTION('',(-0.707106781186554,0.707106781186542,0.));
#731=AXIS2_PLACEMENT_3D('',#728,#729,#730);
#732=PLANE('',#731);
#733=CARTESIAN_POINT('',(3.48291514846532,-5.03709373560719,-2.42));
#734=CARTESIAN_POINT('',(3.48485079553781,-5.01570184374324,-1.47499858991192));
#735=CARTESIAN_POINT('',(3.48675241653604,-4.99427594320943,-0.529997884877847));
#736=CARTESIAN_POINT('',(3.49048760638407,-4.95135612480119,1.36000211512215));
#737=CARTESIAN_POINT('',(3.49232117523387,-4.92986220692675,2.30500141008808));
#738=CARTESIAN_POINT('',(3.49412071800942,-4.90833428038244,3.25));
#739=B_SPLINE_CURVE_WITH_KNOTS('',3,(#733,#734,#735,#736,#737,#738),.UNSPECIFIED.,.F.,.F.,(4,2,
4),(0.,2.83573644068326,5.67147288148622),.UNSPECIFIED.);
#740=CARTESIAN_POINT('',(3.48675928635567,-4.99405549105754,-0.520789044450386));
#741=VERTEX_POINT('',#740);
#742=CARTESIAN_POINT('',(3.49412071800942,-4.90833428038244,3.25));
#743=VERTEX_POINT('',#742);
#744=EDGE_CURVE('E815',#741,#743,#739,.T.);
#745=ORIENTED_EDGE('',*,*,#744,.F.);
#746=DIRECTION('',(0.707106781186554,-0.707106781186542,0.));
#747=VECTOR('',#746,1.);
#748=CARTESIAN_POINT('',(2.9906302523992,-4.49792645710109,-0.520789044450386));
#749=LINE('',#748,#747);
#750=EDGE_CURVE('E563',#741,#123,#749,.F.);
#751=ORIENTED_EDGE('',*,*,#750,.T.);
#752=ORIENTED_EDGE('',*,*,#126,.T.);
#753=DIRECTION('',(0.707106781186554,-0.707106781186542,0.));
#754=VECTOR('',#753,1.);
#755=CARTESIAN_POINT('',(2.82842712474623,-4.24264068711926,3.25));
#756=LINE('',#755,#754);
#757=EDGE_CURVE('E367',#125,#743,#756,.T.);
#758=ORIENTED_EDGE('',*,*,#757,.T.);
#759=EDGE_LOOP('',(#745,#751,#752,#758));
#760=FACE_BOUND('',#759,.T.);
#761=ADVANCED_FACE('F492',(#760),#732,.T.);
#762=CARTESIAN_POINT('',(4.24264068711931,-2.82842712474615,3.25));
#763=DIRECTION('',(-0.706999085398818,-0.706999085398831,-0.0174524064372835));
#764=DIRECTION('',(0.707106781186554,-0.707106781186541,0.));
#765=AXIS2_PLACEMENT_3D('',#762,#763,#764);
#766=PLANE('',#765);
#767=ORIENTED_EDGE('',*,*,#103,.T.);
#768=DIRECTION('',(-0.707106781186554,0.707106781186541,0.));
#769=VECTOR('',#768,1.);
#770=CARTESIAN_POINT('',(4.99818226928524,-3.49088606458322,-0.520789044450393));
#771=LINE('',#770,#769);
#772=CARTESIAN_POINT('',(4.9940554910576,-3.48675928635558,-0.520789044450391));
#773=VERTEX_POINT('',#772);
#774=EDGE_CURVE('E549',#91,#773,#771,.F.);
#775=ORIENTED_EDGE('',*,*,#774,.T.);
#776=CARTESIAN_POINT('',(5.63824588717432,-3.41928915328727,-29.3502427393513));
#777=CARTESIAN_POINT('',(5.57840615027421,-3.42651183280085,-26.6335361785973));
#778=CARTESIAN_POINT('',(5.51833803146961,-3.43350602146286,-23.9168340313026));
#779=CARTESIAN_POINT('',(5.39771827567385,-3.4470106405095,-18.4834394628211));
#780=CARTESIAN_POINT('',(5.337166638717,-3.45352107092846,-15.7667470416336));
#781=CARTESIAN_POINT('',(5.21555308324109,-3.46603139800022,-10.3333724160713));
#782=CARTESIAN_POINT('',(5.15449116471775,-3.47203129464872,-7.61669021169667));
#783=CARTESIAN_POINT('',(5.03182623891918,-3.4834897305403,-2.18333668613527));
#784=CARTESIAN_POINT('',(4.97022323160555,-3.48894826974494,0.533334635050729));
#785=CARTESIAN_POINT('',(4.9083342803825,-3.49412071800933,3.25));
#786=B_SPLINE_CURVE_WITH_KNOTS('',3,(#776,#777,#778,#779,#780,#781,#782,#783,#784,#785),
.UNSPECIFIED.,.F.,.F.,(4,2,2,2,4),(0.,8.15212532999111,16.3042500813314,24.4563749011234,
32.6085002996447),.UNSPECIFIED.);
#787=CARTESIAN_POINT('',(4.9083342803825,-3.49412071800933,3.25));
#788=VERTEX_POINT('',#787);
#789=EDGE_CURVE('E370',#773,#788,#786,.T.);
#790=ORIENTED_EDGE('',*,*,#789,.T.);
#791=DIRECTION('',(-0.707106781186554,0.707106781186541,0.));
#792=VECTOR('',#791,1.);
#793=CARTESIAN_POINT('',(4.24264068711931,-2.82842712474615,3.25));
#794=LINE('',#793,#792);
#795=EDGE_CURVE('E363',#788,#102,#794,.T.);
#796=ORIENTED_EDGE('',*,*,#795,.T.);
#797=EDGE_LOOP('',(#767,#775,#790,#796));
#798=FACE_BOUND('',#797,.T.);
#799=ADVANCED_FACE('F794',(#798),#766,.T.);
#800=CARTESIAN_POINT('',(5.,-0.999999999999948,3.25));
#801=DIRECTION('',(0.,0.999847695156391,-0.0174524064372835));
#802=DIRECTION('',(0.,0.0174524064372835,0.999847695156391));
#803=AXIS2_PLACEMENT_3D('',#800,#801,#802);
#804=PLANE('',#803);
#805=CARTESIAN_POINT('',(6.0245560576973,-1.09897021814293,-2.42));
#806=CARTESIAN_POINT('',(6.01079841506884,-1.08247515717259,-1.47499858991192));
#807=CARTESIAN_POINT('',(5.99699266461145,-1.06598010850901,-0.529997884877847));
#808=CARTESIAN_POINT('',(5.96928494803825,-1.03299003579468,1.36000211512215));
#809=CARTESIAN_POINT('',(5.95538298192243,-1.01649501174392,2.30500141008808));
#810=CARTESIAN_POINT('',(5.94143290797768,-0.999999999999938,3.25));
#811=B_SPLINE_CURVE_WITH_KNOTS('',3,(#805,#806,#807,#808,#809,#810),.UNSPECIFIED.,.F.,.F.,(4,2,
4),(0.,2.83573644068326,5.67147288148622),.UNSPECIFIED.);
#812=CARTESIAN_POINT('',(5.99684163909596,-1.06581936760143,-0.520789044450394));
#813=VERTEX_POINT('',#812);
#814=CARTESIAN_POINT('',(5.94143290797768,-0.999999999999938,3.25));
#815=VERTEX_POINT('',#814);
#816=EDGE_CURVE('E775',#813,#815,#811,.T.);
#817=ORIENTED_EDGE('',*,*,#816,.F.);
#818=DIRECTION('',(1.,0.,0.));
#819=VECTOR('',#818,1.);
#820=CARTESIAN_POINT('',(5.29520923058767,-1.06581936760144,-0.520789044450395));
#821=LINE('',#820,#819);
#822=EDGE_CURVE('E1709',#813,#80,#821,.F.);
#823=ORIENTED_EDGE('',*,*,#822,.T.);
#824=ORIENTED_EDGE('',*,*,#83,.T.);
#825=DIRECTION('',(1.,0.,0.));
#826=VECTOR('',#825,1.);
#827=CARTESIAN_POINT('',(5.,-0.999999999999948,3.25));
#828=LINE('',#827,#826);
#829=EDGE_CURVE('E356',#82,#815,#828,.T.);
#830=ORIENTED_EDGE('',*,*,#829,.T.);
#831=EDGE_LOOP('',(#817,#823,#824,#830));
#832=FACE_BOUND('',#831,.T.);
#833=ADVANCED_FACE('F787',(#832),#804,.T.);
#834=CARTESIAN_POINT('',(5.,1.00000000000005,3.25));
#835=DIRECTION('',(0.,-0.999847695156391,-0.0174524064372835));
#836=DIRECTION('',(0.,0.0174524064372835,-0.999847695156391));
#837=AXIS2_PLACEMENT_3D('',#834,#835,#836);
#838=PLANE('',#837);
#839=ORIENTED_EDGE('',*,*,#55,.T.);
#840=DIRECTION('',(-1.,0.,0.));
#841=VECTOR('',#840,1.);
#842=CARTESIAN_POINT('',(6.00267778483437,1.06581936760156,-0.520789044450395));
#843=LINE('',#842,#841);
#844=CARTESIAN_POINT('',(5.99684163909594,1.06581936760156,-0.520789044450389));
#845=VERTEX_POINT('',#844);
#846=EDGE_CURVE('E1717',#43,#845,#843,.F.);
#847=ORIENTED_EDGE('',*,*,#846,.T.);
#848=CARTESIAN_POINT('',(6.40450372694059,1.56885999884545,-29.3399675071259));
#849=CARTESIAN_POINT('',(6.36730875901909,1.52145465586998,-26.6241172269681));
#850=CARTESIAN_POINT('',(6.32979091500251,1.47404938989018,-23.9082713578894));
#851=CARTESIAN_POINT('',(6.25407165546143,1.37923902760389,-18.4765893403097));
#852=CARTESIAN_POINT('',(6.21587023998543,1.33183393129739,-15.760753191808));
#853=CARTESIAN_POINT('',(6.13874601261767,1.23702391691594,-10.3290911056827));
#854=CARTESIAN_POINT('',(6.09982320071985,1.18961899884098,-7.61326516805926));
#855=CARTESIAN_POINT('',(6.02121264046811,1.09480935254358,-2.18162416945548));
#856=CARTESIAN_POINT('',(5.98152489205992,1.04740462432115,0.534190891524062));
#857=CARTESIAN_POINT('',(5.94143290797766,1.00000000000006,3.25));
#858=B_SPLINE_CURVE_WITH_KNOTS('',3,(#848,#849,#850,#851,#852,#853,#854,#855,#856,#857),
.UNSPECIFIED.,.F.,.F.,(4,2,2,2,4),(0.,8.14955588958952,16.2991112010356,24.4486665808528,
32.5982225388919),.UNSPECIFIED.);
#859=CARTESIAN_POINT('',(5.94143290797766,1.00000000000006,3.25));
#860=VERTEX_POINT('',#859);
#861=EDGE_CURVE('E359',#845,#860,#858,.T.);
#862=ORIENTED_EDGE('',*,*,#861,.T.);
#863=DIRECTION('',(-1.,0.,0.));
#864=VECTOR('',#863,1.);
#865=CARTESIAN_POINT('',(5.,1.00000000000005,3.25));
#866=LINE('',#865,#864);
#867=EDGE_CURVE('E352',#860,#54,#866,.T.);
#868=ORIENTED_EDGE('',*,*,#867,.T.);
#869=EDGE_LOOP('',(#839,#847,#862,#868));
#870=FACE_BOUND('',#869,.T.);
#871=ADVANCED_FACE('F782',(#870),#838,.T.);
#872=CARTESIAN_POINT('',(4.24264068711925,2.82842712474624,3.25));
#873=DIRECTION('',(-0.706999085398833,0.706999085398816,-0.0174524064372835));
#874=DIRECTION('',(-0.707106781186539,-0.707106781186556,0.));
#875=AXIS2_PLACEMENT_3D('',#872,#873,#874);
#876=PLANE('',#875);
#877=CARTESIAN_POINT('',(5.03709373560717,3.48291514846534,-2.42));
#878=CARTESIAN_POINT('',(5.01570184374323,3.48485079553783,-1.47499858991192));
#879=CARTESIAN_POINT('',(4.99427594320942,3.48675241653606,-0.529997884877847));
#880=CARTESIAN_POINT('',(4.95135612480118,3.49048760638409,1.36000211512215));
#881=CARTESIAN_POINT('',(4.92986220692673,3.49232117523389,2.30500141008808));
#882=CARTESIAN_POINT('',(4.90833428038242,3.49412071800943,3.25));
#883=B_SPLINE_CURVE_WITH_KNOTS('',3,(#877,#878,#879,#880,#881,#882),.UNSPECIFIED.,.F.,.F.,(4,2,
4),(0.,2.83573644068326,5.67147288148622),.UNSPECIFIED.);
#884=CARTESIAN_POINT('',(4.99405549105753,3.48675928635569,-0.520789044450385));
#885=VERTEX_POINT('',#884);
#886=CARTESIAN_POINT('',(4.90833428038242,3.49412071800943,3.25));
#887=VERTEX_POINT('',#886);
#888=EDGE_CURVE('E327',#885,#887,#883,.T.);
#889=ORIENTED_EDGE('',*,*,#888,.F.);
#890=DIRECTION('',(0.707106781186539,0.707106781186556,0.));
#891=VECTOR('',#890,1.);
#892=CARTESIAN_POINT('',(4.49792645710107,2.99063025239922,-0.520789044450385));
#893=LINE('',#892,#891);
#894=EDGE_CURVE('E523',#885,#32,#893,.F.);
#895=ORIENTED_EDGE('',*,*,#894,.T.);
#896=ORIENTED_EDGE('',*,*,#35,.T.);
#897=DIRECTION('',(0.707106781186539,0.707106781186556,0.));
#898=VECTOR('',#897,1.);
#899=CARTESIAN_POINT('',(4.24264068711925,2.82842712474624,3.25));
#900=LINE('',#899,#898);
#901=EDGE_CURVE('E328',#34,#887,#900,.T.);
#902=ORIENTED_EDGE('',*,*,#901,.T.);
#903=EDGE_LOOP('',(#889,#895,#896,#902));
#904=FACE_BOUND('',#903,.T.);
#905=ADVANCED_FACE('F786',(#904),#876,.T.);
#906=CARTESIAN_POINT('',(2.82842712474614,4.24264068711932,3.25));
#907=DIRECTION('',(0.706999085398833,-0.706999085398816,-0.0174524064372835));
#908=DIRECTION('',(0.707106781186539,0.707106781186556,0.));
#909=AXIS2_PLACEMENT_3D('',#906,#907,#908);
#910=PLANE('',#909);
#911=ORIENTED_EDGE('',*,*,#361,.T.);
#912=DIRECTION('',(-0.707106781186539,-0.707106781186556,0.));
#913=VECTOR('',#912,1.);
#914=CARTESIAN_POINT('',(3.4908860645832,4.99818226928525,-0.520789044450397));
#915=LINE('',#914,#913);
#916=CARTESIAN_POINT('',(3.48675928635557,4.99405549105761,-0.520789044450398));
#917=VERTEX_POINT('',#916);
#918=EDGE_CURVE('E32',#349,#917,#915,.F.);
#919=ORIENTED_EDGE('',*,*,#918,.T.);
#920=CARTESIAN_POINT('',(3.41928915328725,5.63824588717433,-29.3502427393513));
#921=CARTESIAN_POINT('',(3.42651183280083,5.57840615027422,-26.6335361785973));
#922=CARTESIAN_POINT('',(3.43350602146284,5.51833803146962,-23.9168340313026));
#923=CARTESIAN_POINT('',(3.44701064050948,5.39771827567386,-18.4834394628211));
#924=CARTESIAN_POINT('',(3.45352107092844,5.33716663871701,-15.7667470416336));
#925=CARTESIAN_POINT('',(3.4660313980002,5.2155530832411,-10.3333724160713));
#926=CARTESIAN_POINT('',(3.47203129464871,5.15449116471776,-7.61669021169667));
#927=CARTESIAN_POINT('',(3.48348973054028,5.0318262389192,-2.18333668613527));
#928=CARTESIAN_POINT('',(3.48894826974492,4.97022323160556,0.533334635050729));
#929=CARTESIAN_POINT('',(3.49412071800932,4.90833428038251,3.25));
#930=B_SPLINE_CURVE_WITH_KNOTS('',3,(#920,#921,#922,#923,#924,#925,#926,#927,#928,#929),
.UNSPECIFIED.,.F.,.F.,(4,2,2,2,4),(0.,8.15212532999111,16.3042500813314,24.4563749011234,
32.6085002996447),.UNSPECIFIED.);
#931=CARTESIAN_POINT('',(3.49412071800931,4.90833428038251,3.25));
#932=VERTEX_POINT('',#931);
#933=EDGE_CURVE('E320',#917,#932,#930,.T.);
#934=ORIENTED_EDGE('',*,*,#933,.T.);
#935=DIRECTION('',(-0.707106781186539,-0.707106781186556,0.));
#936=VECTOR('',#935,1.);
#937=CARTESIAN_POINT('',(2.82842712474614,4.24264068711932,3.25));
#938=LINE('',#937,#936);
#939=EDGE_CURVE('E324',#932,#360,#938,.T.);
#940=ORIENTED_EDGE('',*,*,#939,.T.);
#941=EDGE_LOOP('',(#911,#919,#934,#940));
#942=FACE_BOUND('',#941,.T.);
#943=ADVANCED_FACE('F322',(#942),#910,.T.);
#944=CARTESIAN_POINT('',(0.,0.,3.25));
#945=DIRECTION('',(0.,0.,1.));
#946=DIRECTION('',(1.,0.,0.));
#947=AXIS2_PLACEMENT_3D('',#944,#945,#946);
#948=PLANE('',#947);
#949=CARTESIAN_POINT('',(0.,0.,3.25));
#950=DIRECTION('',(0.,0.,1.));
#951=DIRECTION('',(1.,0.,0.));
#952=AXIS2_PLACEMENT_3D('',#949,#950,#951);
#953=CIRCLE('',#952,6.39861865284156);
#954=CARTESIAN_POINT('',(6.39861865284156,0.,3.25));
#955=VERTEX_POINT('',#954);
#956=EDGE_CURVE('E25',#955,#955,#953,.T.);
#957=ORIENTED_EDGE('',*,*,#956,.T.);
#958=EDGE_LOOP('',(#957));
#959=FACE_BOUND('',#958,.T.);
#960=ORIENTED_EDGE('',*,*,#901,.F.);
#961=ORIENTED_EDGE('',*,*,#62,.T.);
#962=ORIENTED_EDGE('',*,*,#867,.F.);
#963=CARTESIAN_POINT('',(0.,0.,3.25));
#964=DIRECTION('',(0.,0.,1.));
#965=DIRECTION('',(0.,-1.,0.));
#966=AXIS2_PLACEMENT_3D('',#963,#964,#965);
#967=CIRCLE('',#966,6.025);
#968=EDGE_CURVE('E349',#815,#860,#967,.T.);
#969=ORIENTED_EDGE('',*,*,#968,.F.);
#970=ORIENTED_EDGE('',*,*,#829,.F.);
#971=ORIENTED_EDGE('',*,*,#105,.T.);
#972=ORIENTED_EDGE('',*,*,#795,.F.);
#973=CARTESIAN_POINT('',(0.,0.,3.25));
#974=DIRECTION('',(0.,0.,1.));
#975=DIRECTION('',(-0.707106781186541,-0.707106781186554,0.));
#976=AXIS2_PLACEMENT_3D('',#973,#974,#975);
#977=CIRCLE('',#976,6.025);
#978=EDGE_CURVE('E360',#743,#788,#977,.T.);
#979=ORIENTED_EDGE('',*,*,#978,.F.);
#980=ORIENTED_EDGE('',*,*,#757,.F.);
#981=ORIENTED_EDGE('',*,*,#148,.T.);
#982=ORIENTED_EDGE('',*,*,#723,.F.);
#983=CARTESIAN_POINT('',(0.,0.,3.25));
#984=DIRECTION('',(0.,0.,1.));
#985=DIRECTION('',(-1.,0.,0.));
#986=AXIS2_PLACEMENT_3D('',#983,#984,#985);
#987=CIRCLE('',#986,6.025);
#988=EDGE_CURVE('E371',#671,#716,#987,.T.);
#989=ORIENTED_EDGE('',*,*,#988,.F.);
#990=ORIENTED_EDGE('',*,*,#685,.F.);
#991=ORIENTED_EDGE('',*,*,#191,.T.);
#992=ORIENTED_EDGE('',*,*,#651,.F.);
#993=CARTESIAN_POINT('',(0.,0.,3.25));
#994=DIRECTION('',(0.,0.,1.));
#995=DIRECTION('',(-0.707106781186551,0.707106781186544,0.));
#996=AXIS2_PLACEMENT_3D('',#993,#994,#995);
#997=CIRCLE('',#996,6.025);
#998=EDGE_CURVE('E382',#599,#644,#997,.T.);
#999=ORIENTED_EDGE('',*,*,#998,.F.);
#1000=ORIENTED_EDGE('',*,*,#613,.F.);
#1001=ORIENTED_EDGE('',*,*,#234,.T.);
#1002=ORIENTED_EDGE('',*,*,#579,.F.);
#1003=CARTESIAN_POINT('',(0.,0.,3.25));
#1004=DIRECTION('',(0.,0.,1.));
#1005=DIRECTION('',(0.,1.,0.));
#1006=AXIS2_PLACEMENT_3D('',#1003,#1004,#1005);
#1007=CIRCLE('',#1006,6.025);
#1008=EDGE_CURVE('E393',#527,#572,#1007,.T.);
#1009=ORIENTED_EDGE('',*,*,#1008,.F.);
#1010=ORIENTED_EDGE('',*,*,#541,.F.);
#1011=ORIENTED_EDGE('',*,*,#277,.T.);
#1012=ORIENTED_EDGE('',*,*,#507,.F.);
#1013=CARTESIAN_POINT('',(0.,0.,3.25));
#1014=DIRECTION('',(0.,0.,1.));
#1015=DIRECTION('',(0.707106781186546,0.707106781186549,0.));
#1016=AXIS2_PLACEMENT_3D('',#1013,#1014,#1015);
#1017=CIRCLE('',#1016,6.025);
#1018=EDGE_CURVE('E404',#455,#500,#1017,.T.);
#1019=ORIENTED_EDGE('',*,*,#1018,.F.);
#1020=ORIENTED_EDGE('',*,*,#469,.F.);
#1021=ORIENTED_EDGE('',*,*,#320,.T.);
#1022=ORIENTED_EDGE('',*,*,#435,.F.);
#1023=CARTESIAN_POINT('',(0.,0.,3.25));
#1024=DIRECTION('',(0.,0.,1.));
#1025=DIRECTION('',(1.,0.,0.));
#1026=AXIS2_PLACEMENT_3D('',#1023,#1024,#1025);
#1027=CIRCLE('',#1026,6.025);
#1028=EDGE_CURVE('E415',#383,#428,#1027,.T.);
#1029=ORIENTED_EDGE('',*,*,#1028,.F.);
#1030=ORIENTED_EDGE('',*,*,#397,.F.);
#1031=ORIENTED_EDGE('',*,*,#363,.T.);
#1032=ORIENTED_EDGE('',*,*,#939,.F.);
#1033=CARTESIAN_POINT('',(0.,0.,3.25));
#1034=DIRECTION('',(0.,0.,1.));
#1035=DIRECTION('',(0.707106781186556,-0.707106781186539,0.));
#1036=AXIS2_PLACEMENT_3D('',#1033,#1034,#1035);
#1037=CIRCLE('',#1036,6.025);
#1038=EDGE_CURVE('E331',#887,#932,#1037,.T.);
#1039=ORIENTED_EDGE('',*,*,#1038,.F.);
#1040=EDGE_LOOP('',(#960,#961,#962,#969,#970,#971,#972,#979,#980,#981,#982,#989,#990,#991,#992,
#999,#1000,#1001,#1002,#1009,#1010,#1011,#1012,#1019,#1020,#1021,#1022,#1029,#1030,#1031,#1032,#1039));
#1041=FACE_BOUND('',#1040,.T.);
#1042=ADVANCED_FACE('F341',(#959,#1041),#948,.T.);
#1043=CARTESIAN_POINT('',(0.,0.,-2.42));
#1044=DIRECTION('',(0.,0.,-1.));
#1045=DIRECTION('',(-1.,0.,0.));
#1046=AXIS2_PLACEMENT_3D('',#1043,#1044,#1045);
#1047=PLANE('',#1046);
#1048=CARTESIAN_POINT('',(0.,0.,-2.42));
#1049=DIRECTION('',(0.,0.,-1.));
#1050=DIRECTION('',(-1.,0.,0.));
#1051=AXIS2_PLACEMENT_3D('',#1048,#1049,#1050);
#1052=CIRCLE('',#1051,6.12397021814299);
#1053=CARTESIAN_POINT('',(-6.12397021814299,0.,-2.42));
#1054=VERTEX_POINT('',#1053);
#1055=EDGE_CURVE('E425',#1054,#1054,#1052,.F.);
#1056=ORIENTED_EDGE('',*,*,#1055,.T.);
#1057=EDGE_LOOP('',(#1056));
#1058=FACE_BOUND('',#1057,.T.);
#1059=CARTESIAN_POINT('',(0.,0.,-2.42));
#1060=DIRECTION('',(0.,0.,-1.));
#1061=DIRECTION('',(-1.,0.,0.));
#1062=AXIS2_PLACEMENT_3D('',#1059,#1060,#1061);
#1063=CIRCLE('',#1062,6.95775874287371);
#1064=CARTESIAN_POINT('',(-6.95775874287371,0.,-2.42));
#1065=VERTEX_POINT('',#1064);
#1066=EDGE_CURVE('E432',#1065,#1065,#1063,.T.);
#1067=ORIENTED_EDGE('',*,*,#1066,.T.);
#1068=EDGE_LOOP('',(#1067));
#1069=FACE_BOUND('',#1068,.T.);
#1070=ADVANCED_FACE('F1204',(#1058,#1069),#1047,.T.);
#1071=CARTESIAN_POINT('',(0.,0.,3.25));
#1072=DIRECTION('',(0.,0.,-1.));
#1073=DIRECTION('',(-1.,0.,0.));
#1074=AXIS2_PLACEMENT_3D('',#1071,#1072,#1073);
#1075=CYLINDRICAL_SURFACE('',#1074,6.51);
#1076=CARTESIAN_POINT('',(0.,0.,1.50000000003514));
#1077=DIRECTION('',(0.,0.,1.));
#1078=DIRECTION('',(1.,0.,0.));
#1079=AXIS2_PLACEMENT_3D('',#1076,#1077,#1078);
#1080=CIRCLE('',#1079,6.51);
#1081=CARTESIAN_POINT('',(6.51,0.,1.50000000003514));
#1082=VERTEX_POINT('',#1081);
#1083=EDGE_CURVE('E438',#1082,#1082,#1080,.F.);
#1084=ORIENTED_EDGE('',*,*,#1083,.T.);
#1085=EDGE_LOOP('',(#1084));
#1086=FACE_BOUND('',#1085,.T.);
#1087=CARTESIAN_POINT('',(0.,0.,0.));
#1088=DIRECTION('',(0.,0.,-1.));
#1089=DIRECTION('',(-1.,0.,0.));
#1090=AXIS2_PLACEMENT_3D('',#1087,#1088,#1089);
#1091=CIRCLE('',#1090,6.51);
#1092=CARTESIAN_POINT('',(-6.51,0.,0.));
#1093=VERTEX_POINT('',#1092);
#1094=EDGE_CURVE('E435',#1093,#1093,#1091,.T.);
#1095=ORIENTED_EDGE('',*,*,#1094,.F.);
#1096=EDGE_LOOP('',(#1095));
#1097=FACE_BOUND('',#1096,.T.);
#1098=ADVANCED_FACE('F1198',(#1086,#1097),#1075,.T.);
#1099=CARTESIAN_POINT('',(0.,0.,3.25));
#1100=DIRECTION('',(0.,0.,-1.));
#1101=DIRECTION('',(-1.,0.,0.));
#1102=AXIS2_PLACEMENT_3D('',#1099,#1100,#1101);
#1103=CONICAL_SURFACE('',#1102,6.48861865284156,0.0122173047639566);
#1104=CARTESIAN_POINT('',(0.,0.,3.05001492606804));
#1105=DIRECTION('',(0.,0.,1.));
#1106=DIRECTION('',(1.,0.,0.));
#1107=AXIS2_PLACEMENT_3D('',#1104,#1105,#1106);
#1108=CIRCLE('',#1107,6.4910620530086);
#1109=CARTESIAN_POINT('',(6.4910620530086,0.,3.05001492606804));
#1110=VERTEX_POINT('',#1109);
#1111=EDGE_CURVE('E11',#1110,#1110,#1108,.F.);
#1112=ORIENTED_EDGE('',*,*,#1111,.T.);
#1113=EDGE_LOOP('',(#1112));
#1114=FACE_BOUND('',#1113,.T.);
#1115=ORIENTED_EDGE('',*,*,#1083,.F.);
#1116=EDGE_LOOP('',(#1115));
#1117=FACE_BOUND('',#1116,.T.);
#1118=ADVANCED_FACE('F1194',(#1114,#1117),#1103,.T.);
#1119=CARTESIAN_POINT('',(0.,0.,0.));
#1120=DIRECTION('',(0.,0.,-1.));
#1121=DIRECTION('',(-1.,0.,0.));
#1122=AXIS2_PLACEMENT_3D('',#1119,#1120,#1121);
#1123=PLANE('',#1122);
#1124=CARTESIAN_POINT('',(0.,0.,0.));
#1125=DIRECTION('',(0.,0.,-1.));
#1126=DIRECTION('',(-1.,0.,0.));
#1127=AXIS2_PLACEMENT_3D('',#1124,#1125,#1126);
#1128=CIRCLE('',#1127,7.);
#1129=CARTESIAN_POINT('',(-7.,0.,0.));
#1130=VERTEX_POINT('',#1129);
#1131=EDGE_CURVE('E427',#1130,#1130,#1128,.T.);
#1132=ORIENTED_EDGE('',*,*,#1131,.F.);
#1133=EDGE_LOOP('',(#1132));
#1134=FACE_BOUND('',#1133,.T.);
#1135=ORIENTED_EDGE('',*,*,#1094,.T.);
#1136=EDGE_LOOP('',(#1135));
#1137=FACE_BOUND('',#1136,.T.);
#1138=ADVANCED_FACE('F1197',(#1134,#1137),#1123,.F.);
#1139=CARTESIAN_POINT('',(0.,0.,0.));
#1140=DIRECTION('',(0.,0.,1.));
#1141=DIRECTION('',(-1.,0.,0.));
#1142=AXIS2_PLACEMENT_3D('',#1139,#1140,#1141);
#1143=CONICAL_SURFACE('',#1142,7.,0.0174532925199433);
#1144=ORIENTED_EDGE('',*,*,#1066,.F.);
#1145=EDGE_LOOP('',(#1144));
#1146=FACE_BOUND('',#1145,.T.);
#1147=ORIENTED_EDGE('',*,*,#1131,.T.);
#1148=EDGE_LOOP('',(#1147));
#1149=FACE_BOUND('',#1148,.T.);
#1150=ADVANCED_FACE('F1209',(#1146,#1149),#1143,.T.);
#1151=CARTESIAN_POINT('',(0.,0.,3.25));
#1152=DIRECTION('',(0.,0.,-1.));
#1153=DIRECTION('',(1.,0.,0.));
#1154=AXIS2_PLACEMENT_3D('',#1151,#1152,#1153);
#1155=CONICAL_SURFACE('',#1154,6.025,0.0174532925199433);
#1156=CARTESIAN_POINT('',(0.,0.,-0.92));
#1157=DIRECTION('',(0.,0.,-1.));
#1158=DIRECTION('',(-1.,0.,0.));
#1159=AXIS2_PLACEMENT_3D('',#1156,#1157,#1158);
#1160=CIRCLE('',#1159,6.09778762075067);
#1161=CARTESIAN_POINT('',(1.17278762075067,5.98394377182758,-0.92));
#1162=VERTEX_POINT('',#1161);
#1163=CARTESIAN_POINT('',(3.4020011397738,5.06057329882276,-0.92));
#1164=VERTEX_POINT('',#1163);
#1165=EDGE_CURVE('E1102',#1162,#1164,#1160,.T.);
#1166=ORIENTED_EDGE('',*,*,#1165,.F.);
#1167=CARTESIAN_POINT('',(0.393924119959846,0.,1.98675815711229));
#1168=DIRECTION('',(0.965925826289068,0.,0.258819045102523));
#1169=DIRECTION('',(0.258819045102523,0.,-0.965925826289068));
#1170=AXIS2_PLACEMENT_3D('',#1167,#1168,#1169);
#1171=ELLIPSE('',#1170,23.3640069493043,6.03420559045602);
#1172=EDGE_CURVE('E40',#1162,#381,#1171,.T.);
#1173=ORIENTED_EDGE('',*,*,#1172,.T.);
#1174=ORIENTED_EDGE('',*,*,#384,.T.);
#1175=ORIENTED_EDGE('',*,*,#1028,.T.);
#1176=ORIENTED_EDGE('',*,*,#429,.F.);
#1177=CARTESIAN_POINT('',(-0.393924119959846,0.,1.98675815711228));
#1178=DIRECTION('',(-0.965925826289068,0.,0.258819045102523));
#1179=DIRECTION('',(-0.258819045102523,0.,-0.965925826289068));
#1180=AXIS2_PLACEMENT_3D('',#1177,#1178,#1179);
#1181=ELLIPSE('',#1180,23.3640069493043,6.03420559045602);
#1182=CARTESIAN_POINT('',(-1.17278762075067,5.98394377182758,-0.92));
#1183=VERTEX_POINT('',#1182);
#1184=EDGE_CURVE('E1145',#413,#1183,#1181,.T.);
#1185=ORIENTED_EDGE('',*,*,#1184,.T.);
#1186=CARTESIAN_POINT('',(-3.40200113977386,5.06057329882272,-0.92));
#1187=VERTEX_POINT('',#1186);
#1188=EDGE_CURVE('E1105',#1187,#1183,#1160,.T.);
#1189=ORIENTED_EDGE('',*,*,#1188,.F.);
#1190=CARTESIAN_POINT('',(0.278546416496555,0.278546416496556,1.9867581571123));
#1191=DIRECTION('',(0.683012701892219,0.683012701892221,0.258819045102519));
#1192=DIRECTION('',(0.183012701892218,0.183012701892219,-0.965925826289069));
#1193=AXIS2_PLACEMENT_3D('',#1190,#1191,#1192);
#1194=ELLIPSE('',#1193,23.3640069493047,6.03420559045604);
#1195=EDGE_CURVE('E1170',#1187,#453,#1194,.T.);
#1196=ORIENTED_EDGE('',*,*,#1195,.T.);
#1197=ORIENTED_EDGE('',*,*,#456,.T.);
#1198=ORIENTED_EDGE('',*,*,#1018,.T.);
#1199=ORIENTED_EDGE('',*,*,#501,.F.);
#1200=CARTESIAN_POINT('',(-0.278546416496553,-0.278546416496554,1.98675815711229));
#1201=DIRECTION('',(-0.683012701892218,-0.683012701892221,0.258819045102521));
#1202=DIRECTION('',(-0.183012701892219,-0.18301270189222,-0.965925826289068));
#1203=AXIS2_PLACEMENT_3D('',#1200,#1201,#1202);
#1204=ELLIPSE('',#1203,23.3640069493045,6.03420559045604);
#1205=CARTESIAN_POINT('',(-5.06057329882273,3.40200113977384,-0.92));
#1206=VERTEX_POINT('',#1205);
#1207=EDGE_CURVE('E1172',#485,#1206,#1204,.T.);
#1208=ORIENTED_EDGE('',*,*,#1207,.T.);
#1209=CARTESIAN_POINT('',(-5.98394377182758,1.17278762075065,-0.92));
#1210=VERTEX_POINT('',#1209);
#1211=EDGE_CURVE('E338',#1210,#1206,#1160,.T.);
#1212=ORIENTED_EDGE('',*,*,#1211,.F.);
#1213=CARTESIAN_POINT('',(0.,0.393924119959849,1.98675815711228));
#1214=DIRECTION('',(0.,0.965925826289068,0.258819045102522));
#1215=DIRECTION('',(0.,0.258819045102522,-0.965925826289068));
#1216=AXIS2_PLACEMENT_3D('',#1213,#1214,#1215);
#1217=ELLIPSE('',#1216,23.3640069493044,6.03420559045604);
#1218=EDGE_CURVE('E1175',#1210,#525,#1217,.T.);
#1219=ORIENTED_EDGE('',*,*,#1218,.T.);
#1220=ORIENTED_EDGE('',*,*,#528,.T.);
#1221=ORIENTED_EDGE('',*,*,#1008,.T.);
#1222=ORIENTED_EDGE('',*,*,#573,.F.);
#1223=CARTESIAN_POINT('',(0.,-0.393924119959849,1.98675815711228));
#1224=DIRECTION('',(0.,-0.965925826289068,0.258819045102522));
#1225=DIRECTION('',(0.,-0.258819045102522,-0.965925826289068));
#1226=AXIS2_PLACEMENT_3D('',#1223,#1224,#1225);
#1227=ELLIPSE('',#1226,23.3640069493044,6.03420559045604);
#1228=CARTESIAN_POINT('',(-5.98394377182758,-1.17278762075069,-0.92));
#1229=VERTEX_POINT('',#1228);
#1230=EDGE_CURVE('E1288',#557,#1229,#1227,.T.);
#1231=ORIENTED_EDGE('',*,*,#1230,.T.);
#1232=CARTESIAN_POINT('',(-5.0605732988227,-3.40200113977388,-0.92));
#1233=VERTEX_POINT('',#1232);
#1234=EDGE_CURVE('E1119',#1233,#1229,#1160,.T.);
#1235=ORIENTED_EDGE('',*,*,#1234,.F.);
#1236=CARTESIAN_POINT('',(-0.278546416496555,0.278546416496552,1.9867581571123));
#1237=DIRECTION('',(-0.683012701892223,0.683012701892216,0.25881904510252));
#1238=DIRECTION('',(-0.18301270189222,0.183012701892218,-0.965925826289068));
#1239=AXIS2_PLACEMENT_3D('',#1236,#1237,#1238);
#1240=ELLIPSE('',#1239,23.3640069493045,6.03420559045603);
#1241=EDGE_CURVE('E1281',#1233,#597,#1240,.T.);
#1242=ORIENTED_EDGE('',*,*,#1241,.T.);
#1243=ORIENTED_EDGE('',*,*,#600,.T.);
#1244=ORIENTED_EDGE('',*,*,#998,.T.);
#1245=ORIENTED_EDGE('',*,*,#645,.F.);
#1246=CARTESIAN_POINT('',(0.278546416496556,-0.278546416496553,1.9867581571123));
#1247=DIRECTION('',(0.683012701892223,-0.683012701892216,0.25881904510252));
#1248=DIRECTION('',(0.18301270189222,-0.183012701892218,-0.965925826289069));
#1249=AXIS2_PLACEMENT_3D('',#1246,#1247,#1248);
#1250=ELLIPSE('',#1249,23.3640069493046,6.03420559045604);
#1251=CARTESIAN_POINT('',(-3.40200113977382,-5.06057329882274,-0.92));
#1252=VERTEX_POINT('',#1251);
#1253=EDGE_CURVE('E1284',#629,#1252,#1250,.T.);
#1254=ORIENTED_EDGE('',*,*,#1253,.T.);
#1255=CARTESIAN_POINT('',(-1.17278762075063,-5.98394377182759,-0.92));
#1256=VERTEX_POINT('',#1255);
#1257=EDGE_CURVE('E1114',#1256,#1252,#1160,.T.);
#1258=ORIENTED_EDGE('',*,*,#1257,.F.);
#1259=CARTESIAN_POINT('',(-0.393924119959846,0.,1.98675815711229));
#1260=DIRECTION('',(-0.965925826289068,0.,0.258819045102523));
#1261=DIRECTION('',(-0.258819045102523,0.,-0.965925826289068));
#1262=AXIS2_PLACEMENT_3D('',#1259,#1260,#1261);
#1263=ELLIPSE('',#1262,23.3640069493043,6.03420559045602);
#1264=EDGE_CURVE('E1286',#1256,#669,#1263,.T.);
#1265=ORIENTED_EDGE('',*,*,#1264,.T.);
#1266=ORIENTED_EDGE('',*,*,#672,.T.);
#1267=ORIENTED_EDGE('',*,*,#988,.T.);
#1268=ORIENTED_EDGE('',*,*,#717,.F.);
#1269=CARTESIAN_POINT('',(0.393924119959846,0.,1.98675815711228));
#1270=DIRECTION('',(0.965925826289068,0.,0.258819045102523));
#1271=DIRECTION('',(0.258819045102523,0.,-0.965925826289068));
#1272=AXIS2_PLACEMENT_3D('',#1269,#1270,#1271);
#1273=ELLIPSE('',#1272,23.3640069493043,6.03420559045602);
#1274=CARTESIAN_POINT('',(1.17278762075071,-5.98394377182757,-0.92));
#1275=VERTEX_POINT('',#1274);
#1276=EDGE_CURVE('E1290',#701,#1275,#1273,.T.);
#1277=ORIENTED_EDGE('',*,*,#1276,.T.);
#1278=CARTESIAN_POINT('',(3.4020011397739,-5.06057329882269,-0.92));
#1279=VERTEX_POINT('',#1278);
#1280=EDGE_CURVE('E1107',#1279,#1275,#1160,.T.);
#1281=ORIENTED_EDGE('',*,*,#1280,.F.);
#1282=CARTESIAN_POINT('',(-0.27854641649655,-0.278546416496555,1.9867581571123));
#1283=DIRECTION('',(-0.683012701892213,-0.683012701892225,0.258819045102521));
#1284=DIRECTION('',(-0.183012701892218,-0.183012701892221,-0.965925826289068));
#1285=AXIS2_PLACEMENT_3D('',#1282,#1283,#1284);
#1286=ELLIPSE('',#1285,23.3640069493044,6.03420559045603);
#1287=EDGE_CURVE('E1699',#1279,#741,#1286,.T.);
#1288=ORIENTED_EDGE('',*,*,#1287,.T.);
#1289=ORIENTED_EDGE('',*,*,#744,.T.);
#1290=ORIENTED_EDGE('',*,*,#978,.T.);
#1291=ORIENTED_EDGE('',*,*,#789,.F.);
#1292=CARTESIAN_POINT('',(0.278546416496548,0.278546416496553,1.98675815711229));
#1293=DIRECTION('',(0.683012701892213,0.683012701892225,0.258819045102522));
#1294=DIRECTION('',(0.183012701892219,0.183012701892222,-0.965925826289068));
#1295=AXIS2_PLACEMENT_3D('',#1292,#1293,#1294);
#1296=ELLIPSE('',#1295,23.3640069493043,6.03420559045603);
#1297=CARTESIAN_POINT('',(5.06057329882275,-3.40200113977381,-0.92));
#1298=VERTEX_POINT('',#1297);
#1299=EDGE_CURVE('E1700',#773,#1298,#1296,.T.);
#1300=ORIENTED_EDGE('',*,*,#1299,.T.);
#1301=CARTESIAN_POINT('',(5.98394377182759,-1.1727876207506,-0.92));
#1302=VERTEX_POINT('',#1301);
#1303=EDGE_CURVE('E1103',#1302,#1298,#1160,.T.);
#1304=ORIENTED_EDGE('',*,*,#1303,.F.);
#1305=CARTESIAN_POINT('',(0.,-0.393924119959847,1.98675815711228));
#1306=DIRECTION('',(0.,-0.965925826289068,0.258819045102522));
#1307=DIRECTION('',(0.,-0.258819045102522,-0.965925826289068));
#1308=AXIS2_PLACEMENT_3D('',#1305,#1306,#1307);
#1309=ELLIPSE('',#1308,23.3640069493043,6.03420559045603);
#1310=EDGE_CURVE('E1704',#1302,#813,#1309,.T.);
#1311=ORIENTED_EDGE('',*,*,#1310,.T.);
#1312=ORIENTED_EDGE('',*,*,#816,.T.);
#1313=ORIENTED_EDGE('',*,*,#968,.T.);
#1314=ORIENTED_EDGE('',*,*,#861,.F.);
#1315=CARTESIAN_POINT('',(0.,0.393924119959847,1.98675815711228));
#1316=DIRECTION('',(0.,0.965925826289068,0.258819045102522));
#1317=DIRECTION('',(0.,0.258819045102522,-0.965925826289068));
#1318=AXIS2_PLACEMENT_3D('',#1315,#1316,#1317);
#1319=ELLIPSE('',#1318,23.3640069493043,6.03420559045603);
#1320=CARTESIAN_POINT('',(5.98394377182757,1.17278762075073,-0.92));
#1321=VERTEX_POINT('',#1320);
#1322=EDGE_CURVE('E1101',#845,#1321,#1319,.T.);
#1323=ORIENTED_EDGE('',*,*,#1322,.T.);
#1324=CARTESIAN_POINT('',(5.06057329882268,3.40200113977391,-0.92));
#1325=VERTEX_POINT('',#1324);
#1326=EDGE_CURVE('E1093',#1325,#1321,#1160,.T.);
#1327=ORIENTED_EDGE('',*,*,#1326,.F.);
#1328=CARTESIAN_POINT('',(0.278546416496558,-0.278546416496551,1.9867581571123));
#1329=DIRECTION('',(0.683012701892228,-0.683012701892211,0.25881904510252));
#1330=DIRECTION('',(0.183012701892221,-0.183012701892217,-0.965925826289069));
#1331=AXIS2_PLACEMENT_3D('',#1328,#1329,#1330);
#1332=ELLIPSE('',#1331,23.3640069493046,6.03420559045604);
#1333=EDGE_CURVE('E1098',#1325,#885,#1332,.T.);
#1334=ORIENTED_EDGE('',*,*,#1333,.T.);
#1335=ORIENTED_EDGE('',*,*,#888,.T.);
#1336=ORIENTED_EDGE('',*,*,#1038,.T.);
#1337=ORIENTED_EDGE('',*,*,#933,.F.);
#1338=CARTESIAN_POINT('',(-0.278546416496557,0.27854641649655,1.98675815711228));
#1339=DIRECTION('',(-0.683012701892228,0.683012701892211,0.258819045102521));
#1340=DIRECTION('',(-0.183012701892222,0.183012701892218,-0.965925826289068));
#1341=AXIS2_PLACEMENT_3D('',#1338,#1339,#1340);
#1342=ELLIPSE('',#1341,23.3640069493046,6.03420559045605);
#1343=EDGE_CURVE('E1180',#917,#1164,#1342,.T.);
#1344=ORIENTED_EDGE('',*,*,#1343,.T.);
#1345=EDGE_LOOP('',(#1166,#1173,#1174,#1175,#1176,#1185,#1189,#1196,#1197,#1198,#1199,#1208,
#1212,#1219,#1220,#1221,#1222,#1231,#1235,#1242,#1243,#1244,#1245,#1254,#1258,#1265,#1266,#1267,
#1268,#1277,#1281,#1288,#1289,#1290,#1291,#1300,#1304,#1311,#1312,#1313,#1314,#1323,#1327,#1334,
#1335,#1336,#1337,#1344));
#1346=FACE_BOUND('',#1345,.T.);
#1347=ORIENTED_EDGE('',*,*,#1055,.F.);
#1348=EDGE_LOOP('',(#1347));
#1349=FACE_BOUND('',#1348,.T.);
#1350=ADVANCED_FACE('F332',(#1346,#1349),#1155,.F.);
#1351=CARTESIAN_POINT('',(0.,0.,-0.92));
#1352=DIRECTION('',(0.,0.,-1.));
#1353=DIRECTION('',(-1.,0.,0.));
#1354=AXIS2_PLACEMENT_3D('',#1351,#1352,#1353);
#1355=PLANE('',#1354);
#1356=CARTESIAN_POINT('',(0.,0.,-0.92));
#1357=DIRECTION('',(0.,0.,-1.));
#1358=DIRECTION('',(-1.,0.,0.));
#1359=AXIS2_PLACEMENT_3D('',#1356,#1357,#1358);
#1360=CIRCLE('',#1359,5.40278762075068);
#1361=CARTESIAN_POINT('',(2.89996875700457,4.55854091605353,-0.92));
#1362=VERTEX_POINT('',#1361);
#1363=CARTESIAN_POINT('',(1.17278762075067,5.27396276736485,-0.92));
#1364=VERTEX_POINT('',#1363);
#1365=EDGE_CURVE('E1080',#1362,#1364,#1360,.F.);
#1366=ORIENTED_EDGE('',*,*,#1365,.T.);
#1367=DIRECTION('',(0.,1.,0.));
#1368=VECTOR('',#1367,1.);
#1369=CARTESIAN_POINT('',(1.17278762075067,6.00267778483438,-0.92));
#1370=LINE('',#1369,#1368);
#1371=EDGE_CURVE('E1163',#1364,#1162,#1370,.T.);
#1372=ORIENTED_EDGE('',*,*,#1371,.T.);
#1373=ORIENTED_EDGE('',*,*,#1165,.T.);
#1374=DIRECTION('',(-0.707106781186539,-0.707106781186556,0.));
#1375=VECTOR('',#1374,1.);
#1376=CARTESIAN_POINT('',(2.91499227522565,4.57356443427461,-0.92));
#1377=LINE('',#1376,#1375);
#1378=EDGE_CURVE('E1164',#1164,#1362,#1377,.T.);
#1379=ORIENTED_EDGE('',*,*,#1378,.T.);
#1380=EDGE_LOOP('',(#1366,#1372,#1373,#1379));
#1381=FACE_BOUND('',#1380,.T.);
#1382=ADVANCED_FACE('F1238',(#1381),#1355,.T.);
#1383=CARTESIAN_POINT('',(0.,0.,-0.92));
#1384=DIRECTION('',(0.,0.,-1.));
#1385=DIRECTION('',(-1.,0.,0.));
#1386=AXIS2_PLACEMENT_3D('',#1383,#1384,#1385);
#1387=CIRCLE('',#1386,5.40278762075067);
#1388=CARTESIAN_POINT('',(5.27396276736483,1.17278762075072,-0.92));
#1389=VERTEX_POINT('',#1388);
#1390=CARTESIAN_POINT('',(4.55854091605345,2.89996875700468,-0.92));
#1391=VERTEX_POINT('',#1390);
#1392=EDGE_CURVE('E1096',#1389,#1391,#1387,.F.);
#1393=ORIENTED_EDGE('',*,*,#1392,.T.);
#1394=DIRECTION('',(0.707106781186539,0.707106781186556,0.));
#1395=VECTOR('',#1394,1.);
#1396=CARTESIAN_POINT('',(5.07382024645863,3.41524808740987,-0.92));
#1397=LINE('',#1396,#1395);
#1398=EDGE_CURVE('E1085',#1391,#1325,#1397,.T.);
#1399=ORIENTED_EDGE('',*,*,#1398,.T.);
#1400=ORIENTED_EDGE('',*,*,#1326,.T.);
#1401=DIRECTION('',(-1.,0.,0.));
#1402=VECTOR('',#1401,1.);
#1403=CARTESIAN_POINT('',(5.29520923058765,1.17278762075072,-0.92));
#1404=LINE('',#1403,#1402);
#1405=EDGE_CURVE('E1083',#1321,#1389,#1404,.T.);
#1406=ORIENTED_EDGE('',*,*,#1405,.T.);
#1407=EDGE_LOOP('',(#1393,#1399,#1400,#1406));
#1408=FACE_BOUND('',#1407,.T.);
#1409=ADVANCED_FACE('F1092',(#1408),#1355,.T.);
#1410=CARTESIAN_POINT('',(0.,0.,-0.92));
#1411=DIRECTION('',(0.,0.,-1.));
#1412=DIRECTION('',(-1.,0.,0.));
#1413=AXIS2_PLACEMENT_3D('',#1410,#1411,#1412);
#1414=CIRCLE('',#1413,5.40278762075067);
#1415=CARTESIAN_POINT('',(4.55854091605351,-2.89996875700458,-0.92));
#1416=VERTEX_POINT('',#1415);
#1417=CARTESIAN_POINT('',(5.27396276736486,-1.17278762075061,-0.92));
#1418=VERTEX_POINT('',#1417);
#1419=EDGE_CURVE('E1684',#1416,#1418,#1414,.F.);
#1420=ORIENTED_EDGE('',*,*,#1419,.T.);
#1421=DIRECTION('',(1.,0.,0.));
#1422=VECTOR('',#1421,1.);
#1423=CARTESIAN_POINT('',(6.0026777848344,-1.1727876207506,-0.92));
#1424=LINE('',#1423,#1422);
#1425=EDGE_CURVE('E1713',#1418,#1302,#1424,.T.);
#1426=ORIENTED_EDGE('',*,*,#1425,.T.);
#1427=ORIENTED_EDGE('',*,*,#1303,.T.);
#1428=DIRECTION('',(-0.707106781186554,0.707106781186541,0.));
#1429=VECTOR('',#1428,1.);
#1430=CARTESIAN_POINT('',(4.5735644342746,-2.91499227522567,-0.92));
#1431=LINE('',#1430,#1429);
#1432=EDGE_CURVE('E1714',#1298,#1416,#1431,.T.);
#1433=ORIENTED_EDGE('',*,*,#1432,.T.);
#1434=EDGE_LOOP('',(#1420,#1426,#1427,#1433));
#1435=FACE_BOUND('',#1434,.T.);
#1436=ADVANCED_FACE('F1248',(#1435),#1355,.T.);
#1437=CARTESIAN_POINT('',(0.,0.,-0.92));
#1438=DIRECTION('',(0.,0.,-1.));
#1439=DIRECTION('',(-1.,0.,0.));
#1440=AXIS2_PLACEMENT_3D('',#1437,#1438,#1439);
#1441=CIRCLE('',#1440,5.40278762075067);
#1442=CARTESIAN_POINT('',(1.1727876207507,-5.27396276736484,-0.92));
#1443=VERTEX_POINT('',#1442);
#1444=CARTESIAN_POINT('',(2.89996875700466,-4.55854091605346,-0.92));
#1445=VERTEX_POINT('',#1444);
#1446=EDGE_CURVE('E1051',#1443,#1445,#1441,.F.);
#1447=ORIENTED_EDGE('',*,*,#1446,.T.);
#1448=DIRECTION('',(0.707106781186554,-0.707106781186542,0.));
#1449=VECTOR('',#1448,1.);
#1450=CARTESIAN_POINT('',(3.41524808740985,-5.07382024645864,-0.92));
#1451=LINE('',#1450,#1449);
#1452=EDGE_CURVE('E560',#1445,#1279,#1451,.T.);
#1453=ORIENTED_EDGE('',*,*,#1452,.T.);
#1454=ORIENTED_EDGE('',*,*,#1280,.T.);
#1455=DIRECTION('',(0.,1.,0.));
#1456=VECTOR('',#1455,1.);
#1457=CARTESIAN_POINT('',(1.1727876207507,-5.29520923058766,-0.92));
#1458=LINE('',#1457,#1456);
#1459=EDGE_CURVE('E557',#1275,#1443,#1458,.T.);
#1460=ORIENTED_EDGE('',*,*,#1459,.T.);
#1461=EDGE_LOOP('',(#1447,#1453,#1454,#1460));
#1462=FACE_BOUND('',#1461,.T.);
#1463=ADVANCED_FACE('F1619',(#1462),#1355,.T.);
#1464=CARTESIAN_POINT('',(0.,0.,-0.92));
#1465=DIRECTION('',(0.,0.,-1.));
#1466=DIRECTION('',(-1.,0.,0.));
#1467=AXIS2_PLACEMENT_3D('',#1464,#1465,#1466);
#1468=CIRCLE('',#1467,5.40278762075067);
#1469=CARTESIAN_POINT('',(-2.89996875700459,-4.5585409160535,-0.92));
#1470=VERTEX_POINT('',#1469);
#1471=CARTESIAN_POINT('',(-1.17278762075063,-5.27396276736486,-0.92));
#1472=VERTEX_POINT('',#1471);
#1473=EDGE_CURVE('E1050',#1470,#1472,#1468,.F.);
#1474=ORIENTED_EDGE('',*,*,#1473,.T.);
#1475=DIRECTION('',(0.,-1.,0.));
#1476=VECTOR('',#1475,1.);
#1477=CARTESIAN_POINT('',(-1.17278762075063,-6.00267778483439,-0.92));
#1478=LINE('',#1477,#1476);
#1479=EDGE_CURVE('E1690',#1472,#1256,#1478,.T.);
#1480=ORIENTED_EDGE('',*,*,#1479,.T.);
#1481=ORIENTED_EDGE('',*,*,#1257,.T.);
#1482=DIRECTION('',(0.707106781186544,0.707106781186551,0.));
#1483=VECTOR('',#1482,1.);
#1484=CARTESIAN_POINT('',(-2.91499227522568,-4.57356443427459,-0.92));
#1485=LINE('',#1484,#1483);
#1486=EDGE_CURVE('E1285',#1252,#1470,#1485,.T.);
#1487=ORIENTED_EDGE('',*,*,#1486,.T.);
#1488=EDGE_LOOP('',(#1474,#1480,#1481,#1487));
#1489=FACE_BOUND('',#1488,.T.);
#1490=ADVANCED_FACE('F1260',(#1489),#1355,.T.);
#1491=CARTESIAN_POINT('',(0.,0.,-0.92));
#1492=DIRECTION('',(0.,0.,-1.));
#1493=DIRECTION('',(-1.,0.,0.));
#1494=AXIS2_PLACEMENT_3D('',#1491,#1492,#1493);
#1495=CIRCLE('',#1494,5.40278762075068);
#1496=CARTESIAN_POINT('',(-5.27396276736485,-1.17278762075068,-0.92));
#1497=VERTEX_POINT('',#1496);
#1498=CARTESIAN_POINT('',(-4.55854091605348,-2.89996875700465,-0.92));
#1499=VERTEX_POINT('',#1498);
#1500=EDGE_CURVE('E1063',#1497,#1499,#1495,.F.);
#1501=ORIENTED_EDGE('',*,*,#1500,.T.);
#1502=DIRECTION('',(-0.707106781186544,-0.707106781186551,0.));
#1503=VECTOR('',#1502,1.);
#1504=CARTESIAN_POINT('',(-5.07382024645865,-3.41524808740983,-0.92));
#1505=LINE('',#1504,#1503);
#1506=EDGE_CURVE('E1279',#1499,#1233,#1505,.T.);
#1507=ORIENTED_EDGE('',*,*,#1506,.T.);
#1508=ORIENTED_EDGE('',*,*,#1234,.T.);
#1509=DIRECTION('',(1.,0.,0.));
#1510=VECTOR('',#1509,1.);
#1511=CARTESIAN_POINT('',(-5.29520923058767,-1.17278762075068,-0.92));
#1512=LINE('',#1511,#1510);
#1513=EDGE_CURVE('E1280',#1229,#1497,#1512,.T.);
#1514=ORIENTED_EDGE('',*,*,#1513,.T.);
#1515=EDGE_LOOP('',(#1501,#1507,#1508,#1514));
#1516=FACE_BOUND('',#1515,.T.);
#1517=ADVANCED_FACE('F1255',(#1516),#1355,.T.);
#1518=CARTESIAN_POINT('',(0.,0.,-0.92));
#1519=DIRECTION('',(0.,0.,-1.));
#1520=DIRECTION('',(-1.,0.,0.));
#1521=AXIS2_PLACEMENT_3D('',#1518,#1519,#1520);
#1522=CIRCLE('',#1521,5.40278762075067);
#1523=CARTESIAN_POINT('',(-4.55854091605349,2.89996875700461,-0.92));
#1524=VERTEX_POINT('',#1523);
#1525=CARTESIAN_POINT('',(-5.27396276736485,1.17278762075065,-0.92));
#1526=VERTEX_POINT('',#1525);
#1527=EDGE_CURVE('E1068',#1524,#1526,#1522,.F.);
#1528=ORIENTED_EDGE('',*,*,#1527,.T.);
#1529=DIRECTION('',(-1.,0.,0.));
#1530=VECTOR('',#1529,1.);
#1531=CARTESIAN_POINT('',(-6.00267778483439,1.17278762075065,-0.92));
#1532=LINE('',#1531,#1530);
#1533=EDGE_CURVE('E1263',#1526,#1210,#1532,.T.);
#1534=ORIENTED_EDGE('',*,*,#1533,.T.);
#1535=ORIENTED_EDGE('',*,*,#1211,.T.);
#1536=DIRECTION('',(0.707106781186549,-0.707106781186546,0.));
#1537=VECTOR('',#1536,1.);
#1538=CARTESIAN_POINT('',(-4.57356443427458,2.91499227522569,-0.92));
#1539=LINE('',#1538,#1537);
#1540=EDGE_CURVE('E1264',#1206,#1524,#1539,.T.);
#1541=ORIENTED_EDGE('',*,*,#1540,.T.);
#1542=EDGE_LOOP('',(#1528,#1534,#1535,#1541));
#1543=FACE_BOUND('',#1542,.T.);
#1544=ADVANCED_FACE('F1250',(#1543),#1355,.T.);
#1545=CARTESIAN_POINT('',(0.,0.,-0.92));
#1546=DIRECTION('',(0.,0.,-1.));
#1547=DIRECTION('',(-1.,0.,0.));
#1548=AXIS2_PLACEMENT_3D('',#1545,#1546,#1547);
#1549=CIRCLE('',#1548,5.40278762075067);
#1550=CARTESIAN_POINT('',(-1.17278762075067,5.27396276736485,-0.92));
#1551=VERTEX_POINT('',#1550);
#1552=CARTESIAN_POINT('',(-2.89996875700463,4.55854091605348,-0.92));
#1553=VERTEX_POINT('',#1552);
#1554=EDGE_CURVE('E1074',#1551,#1553,#1549,.F.);
#1555=ORIENTED_EDGE('',*,*,#1554,.T.);
#1556=DIRECTION('',(-0.707106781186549,0.707106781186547,0.));
#1557=VECTOR('',#1556,1.);
#1558=CARTESIAN_POINT('',(-3.41524808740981,5.07382024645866,-0.92));
#1559=LINE('',#1558,#1557);
#1560=EDGE_CURVE('E678',#1553,#1187,#1559,.T.);
#1561=ORIENTED_EDGE('',*,*,#1560,.T.);
#1562=ORIENTED_EDGE('',*,*,#1188,.T.);
#1563=DIRECTION('',(0.,-1.,0.));
#1564=VECTOR('',#1563,1.);
#1565=CARTESIAN_POINT('',(-1.17278762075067,5.29520923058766,-0.92));
#1566=LINE('',#1565,#1564);
#1567=EDGE_CURVE('E675',#1183,#1551,#1566,.T.);
#1568=ORIENTED_EDGE('',*,*,#1567,.T.);
#1569=EDGE_LOOP('',(#1555,#1561,#1562,#1568));
#1570=FACE_BOUND('',#1569,.T.);
#1571=ADVANCED_FACE('F502',(#1570),#1355,.T.);
#1572=CARTESIAN_POINT('',(0.,0.,-0.520789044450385));
#1573=DIRECTION('',(0.,0.,-1.));
#1574=DIRECTION('',(-1.,0.,0.));
#1575=AXIS2_PLACEMENT_3D('',#1572,#1573,#1574);
#1576=CONICAL_SURFACE('',#1575,5.29581936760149,0.261799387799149);
#1577=ORIENTED_EDGE('',*,*,#44,.F.);
#1578=CARTESIAN_POINT('',(4.42173560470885,2.91443940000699,-0.520789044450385));
#1579=CARTESIAN_POINT('',(4.44461287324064,2.9121127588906,-0.587301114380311));
#1580=CARTESIAN_POINT('',(4.46745195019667,2.90974355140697,-0.653824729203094));
#1581=CARTESIAN_POINT('',(4.51305372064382,2.90492000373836,-0.78689504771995));
#1582=CARTESIAN_POINT('',(4.53581641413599,2.90246566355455,-0.853441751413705));
#1583=CARTESIAN_POINT('',(4.55854091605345,2.89996875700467,-0.92));
#1584=B_SPLINE_CURVE_WITH_KNOTS('',3,(#1578,#1579,#1580,#1581,#1582,#1583),.UNSPECIFIED.,.F.,
.F.,(4,2,4),(0.,0.211124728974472,0.422249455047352),.UNSPECIFIED.);
#1585=EDGE_CURVE('E508',#32,#1391,#1584,.T.);
#1586=ORIENTED_EDGE('',*,*,#1585,.T.);
#1587=ORIENTED_EDGE('',*,*,#1392,.F.);
#1588=CARTESIAN_POINT('',(5.27396276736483,1.17278762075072,-0.92));
#1589=CARTESIAN_POINT('',(5.25965969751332,1.15495339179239,-0.853441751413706));
#1590=CARTESIAN_POINT('',(5.24529952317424,1.1371222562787,-0.786895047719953));
#1591=CARTESIAN_POINT('',(5.2164649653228,1.10146617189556,-0.6538247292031));
#1592=CARTESIAN_POINT('',(5.20199058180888,1.08364122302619,-0.587301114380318));
#1593=CARTESIAN_POINT('',(5.18745909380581,1.06581936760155,-0.520789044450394));
#1594=B_SPLINE_CURVE_WITH_KNOTS('',3,(#1588,#1589,#1590,#1591,#1592,#1593),.UNSPECIFIED.,.F.,
.F.,(4,2,4),(0.,0.211124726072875,0.422249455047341),.UNSPECIFIED.);
#1595=EDGE_CURVE('E516',#1389,#43,#1594,.T.);
#1596=ORIENTED_EDGE('',*,*,#1595,.T.);
#1597=EDGE_LOOP('',(#1577,#1586,#1587,#1596));
#1598=FACE_BOUND('',#1597,.T.);
#1599=ADVANCED_FACE('F496',(#1598),#1576,.F.);
#1600=CARTESIAN_POINT('',(0.,0.,-0.520789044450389));
#1601=DIRECTION('',(0.,0.,-1.));
#1602=DIRECTION('',(-1.,0.,0.));
#1603=AXIS2_PLACEMENT_3D('',#1600,#1601,#1602);
#1604=CONICAL_SURFACE('',#1603,5.29581936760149,0.261799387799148);
#1605=ORIENTED_EDGE('',*,*,#92,.F.);
#1606=CARTESIAN_POINT('',(5.18745909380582,-1.06581936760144,-0.520789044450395));
#1607=CARTESIAN_POINT('',(5.20199058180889,-1.08364122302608,-0.587301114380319));
#1608=CARTESIAN_POINT('',(5.21646496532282,-1.10146617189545,-0.653824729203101));
#1609=CARTESIAN_POINT('',(5.24529952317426,-1.13712225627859,-0.786895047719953));
#1610=CARTESIAN_POINT('',(5.25965969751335,-1.15495339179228,-0.853441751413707));
#1611=CARTESIAN_POINT('',(5.27396276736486,-1.17278762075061,-0.92));
#1612=B_SPLINE_CURVE_WITH_KNOTS('',3,(#1606,#1607,#1608,#1609,#1610,#1611),.UNSPECIFIED.,.F.,
.F.,(4,2,4),(0.,0.211124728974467,0.422249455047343),.UNSPECIFIED.);
#1613=EDGE_CURVE('E542',#80,#1418,#1612,.T.);
#1614=ORIENTED_EDGE('',*,*,#1613,.T.);
#1615=ORIENTED_EDGE('',*,*,#1419,.F.);
#1616=CARTESIAN_POINT('',(4.55854091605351,-2.89996875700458,-0.92));
#1617=CARTESIAN_POINT('',(4.53581641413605,-2.90246566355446,-0.853441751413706));
#1618=CARTESIAN_POINT('',(4.51305372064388,-2.90492000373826,-0.786895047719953));
#1619=CARTESIAN_POINT('',(4.46745195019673,-2.90974355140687,-0.6538247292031));
#1620=CARTESIAN_POINT('',(4.44461287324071,-2.91211275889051,-0.587301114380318));
#1621=CARTESIAN_POINT('',(4.42173560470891,-2.91443940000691,-0.520789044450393));
#1622=B_SPLINE_CURVE_WITH_KNOTS('',3,(#1616,#1617,#1618,#1619,#1620,#1621),.UNSPECIFIED.,.F.,
.F.,(4,2,4),(0.,0.211124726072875,0.422249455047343),.UNSPECIFIED.);
#1623=EDGE_CURVE('E550',#1416,#91,#1622,.T.);
#1624=ORIENTED_EDGE('',*,*,#1623,.T.);
#1625=EDGE_LOOP('',(#1605,#1614,#1615,#1624));
#1626=FACE_BOUND('',#1625,.T.);
#1627=ADVANCED_FACE('F501',(#1626),#1604,.F.);
#1628=CARTESIAN_POINT('',(0.,0.,-0.520789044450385));
#1629=DIRECTION('',(0.,0.,-1.));
#1630=DIRECTION('',(-1.,0.,0.));
#1631=AXIS2_PLACEMENT_3D('',#1628,#1629,#1630);
#1632=CONICAL_SURFACE('',#1631,5.29581936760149,0.261799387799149);
#1633=ORIENTED_EDGE('',*,*,#135,.F.);
#1634=CARTESIAN_POINT('',(2.91443940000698,-4.42173560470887,-0.520789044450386));
#1635=CARTESIAN_POINT('',(2.91211275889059,-4.44461287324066,-0.587301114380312));
#1636=CARTESIAN_POINT('',(2.90974355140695,-4.46745195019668,-0.653824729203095));
#1637=CARTESIAN_POINT('',(2.90492000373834,-4.51305372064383,-0.786895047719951));
#1638=CARTESIAN_POINT('',(2.90246566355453,-4.535816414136,-0.853441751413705));
#1639=CARTESIAN_POINT('',(2.89996875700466,-4.55854091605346,-0.92));
#1640=B_SPLINE_CURVE_WITH_KNOTS('',3,(#1634,#1635,#1636,#1637,#1638,#1639),.UNSPECIFIED.,.F.,
.F.,(4,2,4),(0.,0.21112472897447,0.422249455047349),.UNSPECIFIED.);
#1641=EDGE_CURVE('E572',#123,#1445,#1640,.T.);
#1642=ORIENTED_EDGE('',*,*,#1641,.T.);
#1643=ORIENTED_EDGE('',*,*,#1446,.F.);
#1644=CARTESIAN_POINT('',(1.1727876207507,-5.27396276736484,-0.92));
#1645=CARTESIAN_POINT('',(1.15495339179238,-5.25965969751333,-0.853441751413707));
#1646=CARTESIAN_POINT('',(1.13712225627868,-5.24529952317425,-0.786895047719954));
#1647=CARTESIAN_POINT('',(1.10146617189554,-5.21646496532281,-0.653824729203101));
#1648=CARTESIAN_POINT('',(1.08364122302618,-5.20199058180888,-0.58730111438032));
#1649=CARTESIAN_POINT('',(1.06581936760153,-5.18745909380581,-0.520789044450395));
#1650=B_SPLINE_CURVE_WITH_KNOTS('',3,(#1644,#1645,#1646,#1647,#1648,#1649),.UNSPECIFIED.,.F.,
.F.,(4,2,4),(0.,0.211124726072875,0.422249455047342),.UNSPECIFIED.);
#1651=EDGE_CURVE('E565',#1443,#134,#1650,.T.);
#1652=ORIENTED_EDGE('',*,*,#1651,.T.);
#1653=EDGE_LOOP('',(#1633,#1642,#1643,#1652));
#1654=FACE_BOUND('',#1653,.T.);
#1655=ADVANCED_FACE('F578',(#1654),#1632,.F.);
#1656=CARTESIAN_POINT('',(0.,0.,-0.520789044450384));
#1657=DIRECTION('',(0.,0.,-1.));
#1658=DIRECTION('',(-1.,0.,0.));
#1659=AXIS2_PLACEMENT_3D('',#1656,#1657,#1658);
#1660=CONICAL_SURFACE('',#1659,5.29581936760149,0.261799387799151);
#1661=ORIENTED_EDGE('',*,*,#178,.F.);
#1662=CARTESIAN_POINT('',(-1.06581936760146,-5.18745909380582,-0.520789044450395));
#1663=CARTESIAN_POINT('',(-1.0836412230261,-5.20199058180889,-0.587301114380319));
#1664=CARTESIAN_POINT('',(-1.10146617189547,-5.21646496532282,-0.653824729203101));
#1665=CARTESIAN_POINT('',(-1.13712225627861,-5.24529952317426,-0.786895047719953));
#1666=CARTESIAN_POINT('',(-1.1549533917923,-5.25965969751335,-0.853441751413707));
#1667=CARTESIAN_POINT('',(-1.17278762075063,-5.27396276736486,-0.92));
#1668=B_SPLINE_CURVE_WITH_KNOTS('',3,(#1662,#1663,#1664,#1665,#1666,#1667),.UNSPECIFIED.,.F.,
.F.,(4,2,4),(0.,0.211124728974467,0.422249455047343),.UNSPECIFIED.);
#1669=EDGE_CURVE('E597',#166,#1472,#1668,.T.);
#1670=ORIENTED_EDGE('',*,*,#1669,.T.);
#1671=ORIENTED_EDGE('',*,*,#1473,.F.);
#1672=CARTESIAN_POINT('',(-2.89996875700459,-4.5585409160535,-0.92));
#1673=CARTESIAN_POINT('',(-2.90246566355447,-4.53581641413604,-0.853441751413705));
#1674=CARTESIAN_POINT('',(-2.90492000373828,-4.51305372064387,-0.78689504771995));
#1675=CARTESIAN_POINT('',(-2.90974355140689,-4.46745195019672,-0.653824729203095));
#1676=CARTESIAN_POINT('',(-2.91211275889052,-4.4446128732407,-0.587301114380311));
#1677=CARTESIAN_POINT('',(-2.91443940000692,-4.42173560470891,-0.520789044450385));
#1678=B_SPLINE_CURVE_WITH_KNOTS('',3,(#1672,#1673,#1674,#1675,#1676,#1677),.UNSPECIFIED.,.F.,
.F.,(4,2,4),(0.,0.211124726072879,0.42224945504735),.UNSPECIFIED.);
#1679=EDGE_CURVE('E605',#1470,#177,#1678,.T.);
#1680=ORIENTED_EDGE('',*,*,#1679,.T.);
#1681=EDGE_LOOP('',(#1661,#1670,#1671,#1680));
#1682=FACE_BOUND('',#1681,.T.);
#1683=ADVANCED_FACE('F612',(#1682),#1660,.F.);
#1684=CARTESIAN_POINT('',(0.,0.,-0.520789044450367));
#1685=DIRECTION('',(0.,0.,-1.));
#1686=DIRECTION('',(-1.,0.,0.));
#1687=AXIS2_PLACEMENT_3D('',#1684,#1685,#1686);
#1688=CONICAL_SURFACE('',#1687,5.29581936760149,0.261799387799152);
#1689=ORIENTED_EDGE('',*,*,#221,.F.);
#1690=CARTESIAN_POINT('',(-4.42173560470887,-2.91443940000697,-0.520789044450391));
#1691=CARTESIAN_POINT('',(-4.44461287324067,-2.91211275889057,-0.587301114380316));
#1692=CARTESIAN_POINT('',(-4.46745195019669,-2.90974355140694,-0.653824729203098));
#1693=CARTESIAN_POINT('',(-4.51305372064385,-2.90492000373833,-0.786895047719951));
#1694=CARTESIAN_POINT('',(-4.53581641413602,-2.90246566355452,-0.853441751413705));
#1695=CARTESIAN_POINT('',(-4.55854091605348,-2.89996875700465,-0.92));
#1696=B_SPLINE_CURVE_WITH_KNOTS('',3,(#1690,#1691,#1692,#1693,#1694,#1695),.UNSPECIFIED.,.F.,
.F.,(4,2,4),(0.,0.211124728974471,0.422249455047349),.UNSPECIFIED.);
#1697=EDGE_CURVE('E628',#209,#1499,#1696,.T.);
#1698=ORIENTED_EDGE('',*,*,#1697,.T.);
#1699=ORIENTED_EDGE('',*,*,#1500,.F.);
#1700=CARTESIAN_POINT('',(-5.27396276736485,-1.17278762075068,-0.92));
#1701=CARTESIAN_POINT('',(-5.25965969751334,-1.15495339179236,-0.853441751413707));
#1702=CARTESIAN_POINT('',(-5.24529952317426,-1.13712225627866,-0.786895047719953));
#1703=CARTESIAN_POINT('',(-5.21646496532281,-1.10146617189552,-0.6538247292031));
#1704=CARTESIAN_POINT('',(-5.20199058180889,-1.08364122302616,-0.587301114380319));
#1705=CARTESIAN_POINT('',(-5.18745909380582,-1.06581936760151,-0.520789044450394));
#1706=B_SPLINE_CURVE_WITH_KNOTS('',3,(#1700,#1701,#1702,#1703,#1704,#1705),.UNSPECIFIED.,.F.,
.F.,(4,2,4),(0.,0.211124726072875,0.422249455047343),.UNSPECIFIED.);
#1707=EDGE_CURVE('E635',#1497,#220,#1706,.T.);
#1708=ORIENTED_EDGE('',*,*,#1707,.T.);
#1709=EDGE_LOOP('',(#1689,#1698,#1699,#1708));
#1710=FACE_BOUND('',#1709,.T.);
#1711=ADVANCED_FACE('F616',(#1710),#1688,.F.);
#1712=CARTESIAN_POINT('',(0.,0.,-0.520789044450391));
#1713=DIRECTION('',(0.,0.,-1.));
#1714=DIRECTION('',(-1.,0.,0.));
#1715=AXIS2_PLACEMENT_3D('',#1712,#1713,#1714);
#1716=CONICAL_SURFACE('',#1715,5.29581936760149,0.261799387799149);
#1717=ORIENTED_EDGE('',*,*,#264,.F.);
#1718=CARTESIAN_POINT('',(-5.18745909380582,1.06581936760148,-0.520789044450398));
#1719=CARTESIAN_POINT('',(-5.20199058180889,1.08364122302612,-0.587301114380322));
#1720=CARTESIAN_POINT('',(-5.21646496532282,1.10146617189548,-0.653824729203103));
#1721=CARTESIAN_POINT('',(-5.24529952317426,1.13712225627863,-0.786895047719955));
#1722=CARTESIAN_POINT('',(-5.25965969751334,1.15495339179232,-0.853441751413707));
#1723=CARTESIAN_POINT('',(-5.27396276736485,1.17278762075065,-0.92));
#1724=B_SPLINE_CURVE_WITH_KNOTS('',3,(#1718,#1719,#1720,#1721,#1722,#1723),.UNSPECIFIED.,.F.,
.F.,(4,2,4),(0.,0.211124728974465,0.422249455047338),.UNSPECIFIED.);
#1725=EDGE_CURVE('E660',#252,#1526,#1724,.T.);
#1726=ORIENTED_EDGE('',*,*,#1725,.T.);
#1727=ORIENTED_EDGE('',*,*,#1527,.F.);
#1728=CARTESIAN_POINT('',(-4.55854091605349,2.89996875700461,-0.92));
#1729=CARTESIAN_POINT('',(-4.53581641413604,2.90246566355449,-0.853441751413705));
#1730=CARTESIAN_POINT('',(-4.51305372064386,2.90492000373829,-0.78689504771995));
#1731=CARTESIAN_POINT('',(-4.46745195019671,2.9097435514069,-0.653824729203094));
#1732=CARTESIAN_POINT('',(-4.44461287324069,2.91211275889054,-0.587301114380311));
#1733=CARTESIAN_POINT('',(-4.42173560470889,2.91443940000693,-0.520789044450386));
#1734=B_SPLINE_CURVE_WITH_KNOTS('',3,(#1728,#1729,#1730,#1731,#1732,#1733),.UNSPECIFIED.,.F.,
.F.,(4,2,4),(0.,0.211124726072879,0.422249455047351),.UNSPECIFIED.);
#1735=EDGE_CURVE('E668',#1524,#263,#1734,.T.);
#1736=ORIENTED_EDGE('',*,*,#1735,.T.);
#1737=EDGE_LOOP('',(#1717,#1726,#1727,#1736));
#1738=FACE_BOUND('',#1737,.T.);
#1739=ADVANCED_FACE('F622',(#1738),#1716,.F.);
#1740=CARTESIAN_POINT('',(0.,0.,-0.520789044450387));
#1741=DIRECTION('',(0.,0.,-1.));
#1742=DIRECTION('',(-1.,0.,0.));
#1743=AXIS2_PLACEMENT_3D('',#1740,#1741,#1742);
#1744=CONICAL_SURFACE('',#1743,5.29581936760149,0.26179938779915);
#1745=ORIENTED_EDGE('',*,*,#307,.F.);
#1746=CARTESIAN_POINT('',(-2.91443940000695,4.42173560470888,-0.520789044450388));
#1747=CARTESIAN_POINT('',(-2.91211275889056,4.44461287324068,-0.587301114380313));
#1748=CARTESIAN_POINT('',(-2.90974355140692,4.4674519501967,-0.653824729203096));
#1749=CARTESIAN_POINT('',(-2.90492000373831,4.51305372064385,-0.786895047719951));
#1750=CARTESIAN_POINT('',(-2.9024656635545,4.53581641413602,-0.853441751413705));
#1751=CARTESIAN_POINT('',(-2.89996875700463,4.55854091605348,-0.92));
#1752=B_SPLINE_CURVE_WITH_KNOTS('',3,(#1746,#1747,#1748,#1749,#1750,#1751),.UNSPECIFIED.,.F.,
.F.,(4,2,4),(0.,0.21112472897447,0.422249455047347),.UNSPECIFIED.);
#1753=EDGE_CURVE('E690',#295,#1553,#1752,.T.);
#1754=ORIENTED_EDGE('',*,*,#1753,.T.);
#1755=ORIENTED_EDGE('',*,*,#1554,.F.);
#1756=CARTESIAN_POINT('',(-1.17278762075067,5.27396276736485,-0.92));
#1757=CARTESIAN_POINT('',(-1.15495339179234,5.25965969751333,-0.853441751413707));
#1758=CARTESIAN_POINT('',(-1.13712225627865,5.24529952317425,-0.786895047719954));
#1759=CARTESIAN_POINT('',(-1.1014661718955,5.21646496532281,-0.653824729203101));
#1760=CARTESIAN_POINT('',(-1.08364122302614,5.20199058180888,-0.587301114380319));
#1761=CARTESIAN_POINT('',(-1.06581936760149,5.18745909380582,-0.520789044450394));
#1762=B_SPLINE_CURVE_WITH_KNOTS('',3,(#1756,#1757,#1758,#1759,#1760,#1761),.UNSPECIFIED.,.F.,
.F.,(4,2,4),(0.,0.211124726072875,0.422249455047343),.UNSPECIFIED.);
#1763=EDGE_CURVE('E683',#1551,#306,#1762,.T.);
#1764=ORIENTED_EDGE('',*,*,#1763,.T.);
#1765=EDGE_LOOP('',(#1745,#1754,#1755,#1764));
#1766=FACE_BOUND('',#1765,.T.);
#1767=ADVANCED_FACE('F696',(#1766),#1744,.F.);
#1768=CARTESIAN_POINT('',(0.,0.,-0.520789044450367));
#1769=DIRECTION('',(0.,0.,-1.));
#1770=DIRECTION('',(-1.,0.,0.));
#1771=AXIS2_PLACEMENT_3D('',#1768,#1769,#1770);
#1772=CONICAL_SURFACE('',#1771,5.29581936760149,0.261799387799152);
#1773=ORIENTED_EDGE('',*,*,#350,.F.);
#1774=CARTESIAN_POINT('',(1.06581936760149,5.18745909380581,-0.520789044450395));
#1775=CARTESIAN_POINT('',(1.08364122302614,5.20199058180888,-0.587301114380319));
#1776=CARTESIAN_POINT('',(1.1014661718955,5.21646496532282,-0.6538247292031));
#1777=CARTESIAN_POINT('',(1.13712225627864,5.24529952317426,-0.786895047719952));
#1778=CARTESIAN_POINT('',(1.15495339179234,5.25965969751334,-0.853441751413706));
#1779=CARTESIAN_POINT('',(1.17278762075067,5.27396276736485,-0.92));
#1780=B_SPLINE_CURVE_WITH_KNOTS('',3,(#1774,#1775,#1776,#1777,#1778,#1779),.UNSPECIFIED.,.F.,
.F.,(4,2,4),(0.,0.211124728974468,0.422249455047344),.UNSPECIFIED.);
#1781=EDGE_CURVE('E712',#338,#1364,#1780,.T.);
#1782=ORIENTED_EDGE('',*,*,#1781,.T.);
#1783=ORIENTED_EDGE('',*,*,#1365,.F.);
#1784=CARTESIAN_POINT('',(2.89996875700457,4.55854091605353,-0.92));
#1785=CARTESIAN_POINT('',(2.90246566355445,4.53581641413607,-0.853441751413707));
#1786=CARTESIAN_POINT('',(2.90492000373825,4.5130537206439,-0.786895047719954));
#1787=CARTESIAN_POINT('',(2.90974355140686,4.46745195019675,-0.653824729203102));
#1788=CARTESIAN_POINT('',(2.9121127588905,4.44461287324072,-0.58730111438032));
#1789=CARTESIAN_POINT('',(2.9144394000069,4.42173560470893,-0.520789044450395));
#1790=B_SPLINE_CURVE_WITH_KNOTS('',3,(#1784,#1785,#1786,#1787,#1788,#1789),.UNSPECIFIED.,.F.,
.F.,(4,2,4),(0.,0.211124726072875,0.422249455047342),.UNSPECIFIED.);
#1791=EDGE_CURVE('E719',#1362,#349,#1790,.T.);
#1792=ORIENTED_EDGE('',*,*,#1791,.T.);
#1793=EDGE_LOOP('',(#1773,#1782,#1783,#1792));
#1794=FACE_BOUND('',#1793,.T.);
#1795=ADVANCED_FACE('F726',(#1794),#1772,.F.);
#1796=CARTESIAN_POINT('',(0.829286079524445,-0.829286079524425,-0.92));
#1797=DIRECTION('',(0.683012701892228,-0.683012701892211,0.25881904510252));
#1798=DIRECTION('',(0.707106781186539,0.707106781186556,0.));
#1799=AXIS2_PLACEMENT_3D('',#1796,#1797,#1798);
#1800=PLANE('',#1799);
#1801=ORIENTED_EDGE('',*,*,#1585,.F.);
#1802=ORIENTED_EDGE('',*,*,#894,.F.);
#1803=ORIENTED_EDGE('',*,*,#1333,.F.);
#1804=ORIENTED_EDGE('',*,*,#1398,.F.);
#1805=EDGE_LOOP('',(#1801,#1802,#1803,#1804));
#1806=FACE_BOUND('',#1805,.T.);
#1807=ADVANCED_FACE('F530',(#1806),#1800,.F.);
#1808=CARTESIAN_POINT('',(0.,1.17278762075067,-0.92));
#1809=DIRECTION('',(0.,0.965925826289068,0.258819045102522));
#1810=DIRECTION('',(0.,-0.258819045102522,0.965925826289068));
#1811=AXIS2_PLACEMENT_3D('',#1808,#1809,#1810);
#1812=PLANE('',#1811);
#1813=ORIENTED_EDGE('',*,*,#1322,.F.);
#1814=ORIENTED_EDGE('',*,*,#846,.F.);
#1815=ORIENTED_EDGE('',*,*,#1595,.F.);
#1816=ORIENTED_EDGE('',*,*,#1405,.F.);
#1817=EDGE_LOOP('',(#1813,#1814,#1815,#1816));
#1818=FACE_BOUND('',#1817,.T.);
#1819=ADVANCED_FACE('F525',(#1818),#1812,.F.);
#1820=CARTESIAN_POINT('',(0.,-1.17278762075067,-0.92));
#1821=DIRECTION('',(0.,-0.965925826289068,0.258819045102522));
#1822=DIRECTION('',(0.,-0.258819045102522,-0.965925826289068));
#1823=AXIS2_PLACEMENT_3D('',#1820,#1821,#1822);
#1824=PLANE('',#1823);
#1825=ORIENTED_EDGE('',*,*,#1613,.F.);
#1826=ORIENTED_EDGE('',*,*,#822,.F.);
#1827=ORIENTED_EDGE('',*,*,#1310,.F.);
#1828=ORIENTED_EDGE('',*,*,#1425,.F.);
#1829=EDGE_LOOP('',(#1825,#1826,#1827,#1828));
#1830=FACE_BOUND('',#1829,.T.);
#1831=ADVANCED_FACE('F529',(#1830),#1824,.F.);
#1832=CARTESIAN_POINT('',(0.829286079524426,0.829286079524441,-0.92));
#1833=DIRECTION('',(0.683012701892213,0.683012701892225,0.258819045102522));
#1834=DIRECTION('',(-0.707106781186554,0.707106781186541,0.));
#1835=AXIS2_PLACEMENT_3D('',#1832,#1833,#1834);
#1836=PLANE('',#1835);
#1837=ORIENTED_EDGE('',*,*,#1299,.F.);
#1838=ORIENTED_EDGE('',*,*,#774,.F.);
#1839=ORIENTED_EDGE('',*,*,#1623,.F.);
#1840=ORIENTED_EDGE('',*,*,#1432,.F.);
#1841=EDGE_LOOP('',(#1837,#1838,#1839,#1840));
#1842=FACE_BOUND('',#1841,.T.);
#1843=ADVANCED_FACE('F537',(#1842),#1836,.F.);
#1844=CARTESIAN_POINT('',(-0.829286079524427,-0.829286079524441,-0.92));
#1845=DIRECTION('',(-0.683012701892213,-0.683012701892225,0.258819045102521));
#1846=DIRECTION('',(0.707106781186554,-0.707106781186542,0.));
#1847=AXIS2_PLACEMENT_3D('',#1844,#1845,#1846);
#1848=PLANE('',#1847);
#1849=ORIENTED_EDGE('',*,*,#1641,.F.);
#1850=ORIENTED_EDGE('',*,*,#750,.F.);
#1851=ORIENTED_EDGE('',*,*,#1287,.F.);
#1852=ORIENTED_EDGE('',*,*,#1452,.F.);
#1853=EDGE_LOOP('',(#1849,#1850,#1851,#1852));
#1854=FACE_BOUND('',#1853,.T.);
#1855=ADVANCED_FACE('F586',(#1854),#1848,.F.);
#1856=CARTESIAN_POINT('',(1.17278762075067,0.,-0.92));
#1857=DIRECTION('',(0.965925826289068,0.,0.258819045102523));
#1858=DIRECTION('',(0.258819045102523,0.,-0.965925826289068));
#1859=AXIS2_PLACEMENT_3D('',#1856,#1857,#1858);
#1860=PLANE('',#1859);
#1861=ORIENTED_EDGE('',*,*,#1276,.F.);
#1862=ORIENTED_EDGE('',*,*,#702,.F.);
#1863=ORIENTED_EDGE('',*,*,#1651,.F.);
#1864=ORIENTED_EDGE('',*,*,#1459,.F.);
#1865=EDGE_LOOP('',(#1861,#1862,#1863,#1864));
#1866=FACE_BOUND('',#1865,.T.);
#1867=ADVANCED_FACE('F581',(#1866),#1860,.F.);
#1868=CARTESIAN_POINT('',(-1.17278762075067,0.,-0.92));
#1869=DIRECTION('',(-0.965925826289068,0.,0.258819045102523));
#1870=DIRECTION('',(0.258819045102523,0.,0.965925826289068));
#1871=AXIS2_PLACEMENT_3D('',#1868,#1869,#1870);
#1872=PLANE('',#1871);
#1873=ORIENTED_EDGE('',*,*,#1669,.F.);
#1874=ORIENTED_EDGE('',*,*,#678,.F.);
#1875=ORIENTED_EDGE('',*,*,#1264,.F.);
#1876=ORIENTED_EDGE('',*,*,#1479,.F.);
#1877=EDGE_LOOP('',(#1873,#1874,#1875,#1876));
#1878=FACE_BOUND('',#1877,.T.);
#1879=ADVANCED_FACE('F585',(#1878),#1872,.F.);
#1880=CARTESIAN_POINT('',(0.829286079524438,-0.829286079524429,-0.92));
#1881=DIRECTION('',(0.683012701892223,-0.683012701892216,0.25881904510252));
#1882=DIRECTION('',(0.707106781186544,0.707106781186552,0.));
#1883=AXIS2_PLACEMENT_3D('',#1880,#1881,#1882);
#1884=PLANE('',#1883);
#1885=ORIENTED_EDGE('',*,*,#1253,.F.);
#1886=ORIENTED_EDGE('',*,*,#630,.F.);
#1887=ORIENTED_EDGE('',*,*,#1679,.F.);
#1888=ORIENTED_EDGE('',*,*,#1486,.F.);
#1889=EDGE_LOOP('',(#1885,#1886,#1887,#1888));
#1890=FACE_BOUND('',#1889,.T.);
#1891=ADVANCED_FACE('F592',(#1890),#1884,.F.);
#1892=CARTESIAN_POINT('',(-0.829286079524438,0.82928607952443,-0.92));
#1893=DIRECTION('',(-0.683012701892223,0.683012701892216,0.25881904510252));
#1894=DIRECTION('',(-0.707106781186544,-0.707106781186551,0.));
#1895=AXIS2_PLACEMENT_3D('',#1892,#1893,#1894);
#1896=PLANE('',#1895);
#1897=ORIENTED_EDGE('',*,*,#1697,.F.);
#1898=ORIENTED_EDGE('',*,*,#606,.F.);
#1899=ORIENTED_EDGE('',*,*,#1241,.F.);
#1900=ORIENTED_EDGE('',*,*,#1506,.F.);
#1901=EDGE_LOOP('',(#1897,#1898,#1899,#1900));
#1902=FACE_BOUND('',#1901,.T.);
#1903=ADVANCED_FACE('F649',(#1902),#1896,.F.);
#1904=CARTESIAN_POINT('',(0.,-1.17278762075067,-0.92));
#1905=DIRECTION('',(0.,-0.965925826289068,0.258819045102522));
#1906=DIRECTION('',(0.,-0.258819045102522,-0.965925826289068));
#1907=AXIS2_PLACEMENT_3D('',#1904,#1905,#1906);
#1908=PLANE('',#1907);
#1909=ORIENTED_EDGE('',*,*,#1230,.F.);
#1910=ORIENTED_EDGE('',*,*,#558,.F.);
#1911=ORIENTED_EDGE('',*,*,#1707,.F.);
#1912=ORIENTED_EDGE('',*,*,#1513,.F.);
#1913=EDGE_LOOP('',(#1909,#1910,#1911,#1912));
#1914=FACE_BOUND('',#1913,.T.);
#1915=ADVANCED_FACE('F644',(#1914),#1908,.F.);
#1916=CARTESIAN_POINT('',(0.,1.17278762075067,-0.92));
#1917=DIRECTION('',(0.,0.965925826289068,0.258819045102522));
#1918=DIRECTION('',(0.,-0.258819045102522,0.965925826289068));
#1919=AXIS2_PLACEMENT_3D('',#1916,#1917,#1918);
#1920=PLANE('',#1919);
#1921=ORIENTED_EDGE('',*,*,#1725,.F.);
#1922=ORIENTED_EDGE('',*,*,#534,.F.);
#1923=ORIENTED_EDGE('',*,*,#1218,.F.);
#1924=ORIENTED_EDGE('',*,*,#1533,.F.);
#1925=EDGE_LOOP('',(#1921,#1922,#1923,#1924));
#1926=FACE_BOUND('',#1925,.T.);
#1927=ADVANCED_FACE('F648',(#1926),#1920,.F.);
#1928=CARTESIAN_POINT('',(-0.829286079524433,-0.829286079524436,-0.92));
#1929=DIRECTION('',(-0.683012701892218,-0.683012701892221,0.258819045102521));
#1930=DIRECTION('',(0.707106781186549,-0.707106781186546,0.));
#1931=AXIS2_PLACEMENT_3D('',#1928,#1929,#1930);
#1932=PLANE('',#1931);
#1933=ORIENTED_EDGE('',*,*,#1207,.F.);
#1934=ORIENTED_EDGE('',*,*,#486,.F.);
#1935=ORIENTED_EDGE('',*,*,#1735,.F.);
#1936=ORIENTED_EDGE('',*,*,#1540,.F.);
#1937=EDGE_LOOP('',(#1933,#1934,#1935,#1936));
#1938=FACE_BOUND('',#1937,.T.);
#1939=ADVANCED_FACE('F655',(#1938),#1932,.F.);
#1940=CARTESIAN_POINT('',(0.829286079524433,0.829286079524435,-0.92));
#1941=DIRECTION('',(0.683012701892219,0.683012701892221,0.258819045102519));
#1942=DIRECTION('',(-0.707106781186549,0.707106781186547,0.));
#1943=AXIS2_PLACEMENT_3D('',#1940,#1941,#1942);
#1944=PLANE('',#1943);
#1945=ORIENTED_EDGE('',*,*,#1753,.F.);
#1946=ORIENTED_EDGE('',*,*,#462,.F.);
#1947=ORIENTED_EDGE('',*,*,#1195,.F.);
#1948=ORIENTED_EDGE('',*,*,#1560,.F.);
#1949=EDGE_LOOP('',(#1945,#1946,#1947,#1948));
#1950=FACE_BOUND('',#1949,.T.);
#1951=ADVANCED_FACE('F703',(#1950),#1944,.F.);
#1952=CARTESIAN_POINT('',(-1.17278762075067,0.,-0.92));
#1953=DIRECTION('',(-0.965925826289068,0.,0.258819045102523));
#1954=DIRECTION('',(0.258819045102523,0.,0.965925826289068));
#1955=AXIS2_PLACEMENT_3D('',#1952,#1953,#1954);
#1956=PLANE('',#1955);
#1957=ORIENTED_EDGE('',*,*,#1184,.F.);
#1958=ORIENTED_EDGE('',*,*,#414,.F.);
#1959=ORIENTED_EDGE('',*,*,#1763,.F.);
#1960=ORIENTED_EDGE('',*,*,#1567,.F.);
#1961=EDGE_LOOP('',(#1957,#1958,#1959,#1960));
#1962=FACE_BOUND('',#1961,.T.);
#1963=ADVANCED_FACE('F698',(#1962),#1956,.F.);
#1964=CARTESIAN_POINT('',(1.17278762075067,0.,-0.92));
#1965=DIRECTION('',(0.965925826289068,0.,0.258819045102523));
#1966=DIRECTION('',(0.258819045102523,0.,-0.965925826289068));
#1967=AXIS2_PLACEMENT_3D('',#1964,#1965,#1966);
#1968=PLANE('',#1967);
#1969=ORIENTED_EDGE('',*,*,#1781,.F.);
#1970=ORIENTED_EDGE('',*,*,#390,.F.);
#1971=ORIENTED_EDGE('',*,*,#1172,.F.);
#1972=ORIENTED_EDGE('',*,*,#1371,.F.);
#1973=EDGE_LOOP('',(#1969,#1970,#1971,#1972));
#1974=FACE_BOUND('',#1973,.T.);
#1975=ADVANCED_FACE('F702',(#1974),#1968,.F.);
#1976=CARTESIAN_POINT('',(-0.829286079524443,0.829286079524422,-0.92));
#1977=DIRECTION('',(-0.683012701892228,0.683012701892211,0.258819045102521));
#1978=DIRECTION('',(-0.707106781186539,-0.707106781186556,0.));
#1979=AXIS2_PLACEMENT_3D('',#1976,#1977,#1978);
#1980=PLANE('',#1979);
#1981=ORIENTED_EDGE('',*,*,#1343,.F.);
#1982=ORIENTED_EDGE('',*,*,#918,.F.);
#1983=ORIENTED_EDGE('',*,*,#1791,.F.);
#1984=ORIENTED_EDGE('',*,*,#1378,.F.);
#1985=EDGE_LOOP('',(#1981,#1982,#1983,#1984));
#1986=FACE_BOUND('',#1985,.T.);
#1987=ADVANCED_FACE('F708',(#1986),#1980,.F.);
#1988=CARTESIAN_POINT('',(0.,0.,3.25));
#1989=DIRECTION('',(0.,0.,-1.));
#1990=DIRECTION('',(-1.,0.,0.));
#1991=AXIS2_PLACEMENT_3D('',#1988,#1989,#1990);
#1992=CONICAL_SURFACE('',#1991,6.39861865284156,0.432995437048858);
#1993=ORIENTED_EDGE('',*,*,#1111,.F.);
#1994=EDGE_LOOP('',(#1993));
#1995=FACE_BOUND('',#1994,.T.);
#1996=ORIENTED_EDGE('',*,*,#956,.F.);
#1997=EDGE_LOOP('',(#1996));
#1998=FACE_BOUND('',#1997,.T.);
#1999=ADVANCED_FACE('F19',(#1995,#1998),#1992,.T.);
#2000=CLOSED_SHELL('',(#66,#109,#152,#195,#238,#281,#324,#367,#401,#439,#473,#511,#545,#583,
#617,#655,#689,#727,#761,#799,#833,#871,#905,#943,#1042,#1070,#1098,#1118,#1138,#1150,#1350,
#1382,#1409,#1436,#1463,#1490,#1517,#1544,#1571,#1599,#1627,#1655,#1683,#1711,#1739,#1767,#1795,
#1807,#1819,#1831,#1843,#1855,#1867,#1879,#1891,#1903,#1915,#1927,#1939,#1951,#1963,#1975,#1987,#1999));
#2001=MANIFOLD_SOLID_BREP('B1',#2000);
#2002=ADVANCED_BREP_SHAPE_REPRESENTATION('',(#18,#2001),#14);
#2003=SHAPE_DEFINITION_REPRESENTATION(#9,#2002);
ENDSEC;
END-ISO-10303-21;
